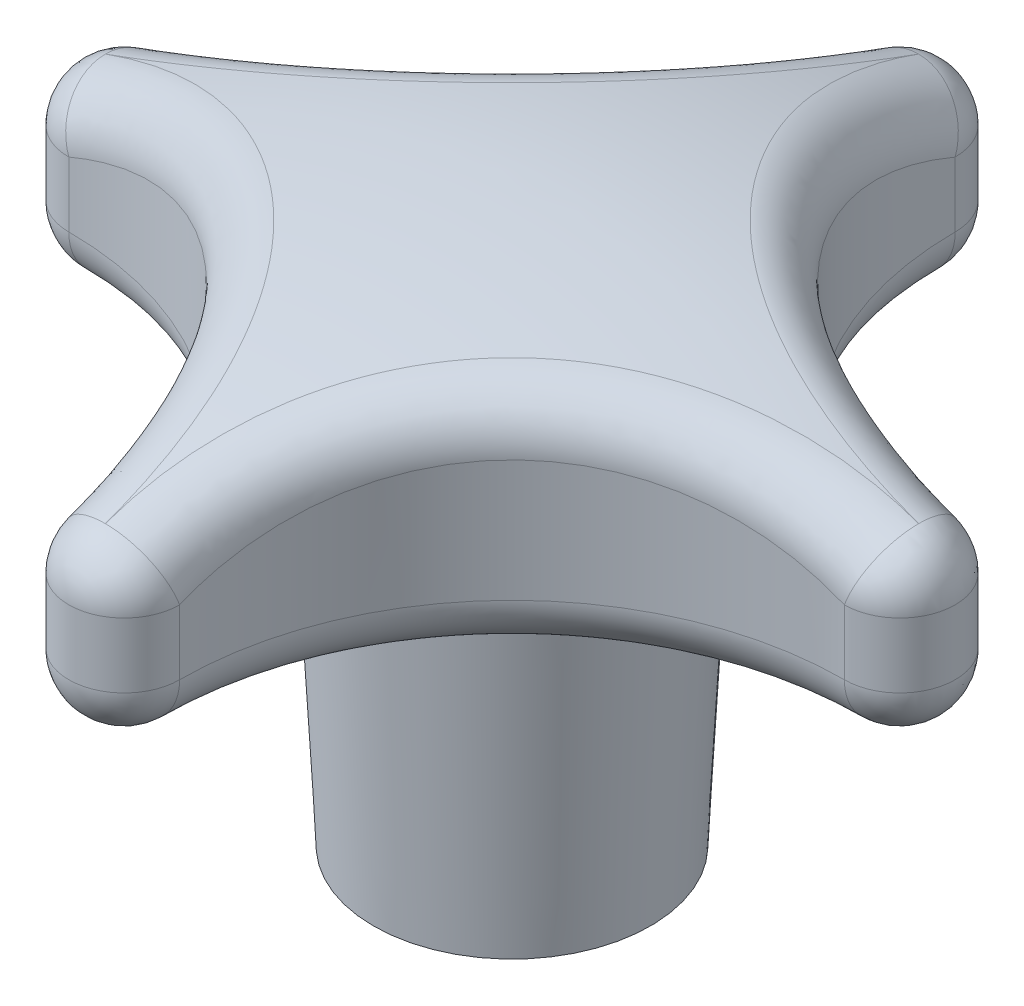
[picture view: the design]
ISO-10303-21;
HEADER;
FILE_DESCRIPTION(('STEP AP214'),'2;1');
FILE_NAME('part.step','',(''),(''),'','','');
FILE_SCHEMA(('AUTOMOTIVE_DESIGN { 1 0 10303 214 1 1 1 1 }'));
ENDSEC;
DATA;
#1=APPLICATION_CONTEXT('core data for automotive mechanical design processes');
#2=APPLICATION_PROTOCOL_DEFINITION('international standard','automotive_design',2000,#1);
#3=PRODUCT_CONTEXT('',#1,'mechanical');
#4=PRODUCT('Part','Part','',(#3));
#5=PRODUCT_RELATED_PRODUCT_CATEGORY('part','',(#4));
#6=PRODUCT_DEFINITION_FORMATION('','',#4);
#7=PRODUCT_DEFINITION_CONTEXT('part definition',#1,'design');
#8=PRODUCT_DEFINITION('design','',#6,#7);
#9=PRODUCT_DEFINITION_SHAPE('','',#8);
#10=(LENGTH_UNIT() NAMED_UNIT(*) SI_UNIT(.MILLI.,.METRE.));
#11=(NAMED_UNIT(*) PLANE_ANGLE_UNIT() SI_UNIT($,.RADIAN.));
#12=(NAMED_UNIT(*) SI_UNIT($,.STERADIAN.) SOLID_ANGLE_UNIT());
#13=UNCERTAINTY_MEASURE_WITH_UNIT(LENGTH_MEASURE(1.E-05),#10,'distance_accuracy_value','');
#14=(GEOMETRIC_REPRESENTATION_CONTEXT(3) GLOBAL_UNCERTAINTY_ASSIGNED_CONTEXT((#13)) GLOBAL_UNIT_ASSIGNED_CONTEXT((#10,
#11,#12)) REPRESENTATION_CONTEXT('',''));
#15=CARTESIAN_POINT('',(0.,0.,0.));
#16=DIRECTION('',(0.,0.,1.));
#17=DIRECTION('',(1.,0.,0.));
#18=AXIS2_PLACEMENT_3D('',#15,#16,#17);
#19=CARTESIAN_POINT('',(0.,-85.7461038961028,0.));
#20=DIRECTION('',(0.,-1.,0.));
#21=DIRECTION('',(1.,0.,0.));
#22=AXIS2_PLACEMENT_3D('',#19,#20,#21);
#23=SPHERICAL_SURFACE('',#22,107.746103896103);
#24=CARTESIAN_POINT('',(-45.4260701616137,5.50948791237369,6.86999713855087));
#25=CARTESIAN_POINT('',(-47.811696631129,10.6709628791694,7.75420284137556));
#26=CARTESIAN_POINT('',(-49.4589084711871,9.95031770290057,2.28783101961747));
#27=CARTESIAN_POINT('',(-44.6147524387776,6.00713444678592,6.56920938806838));
#28=CARTESIAN_POINT('',(-46.9657144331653,11.1176727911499,7.36275900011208));
#29=CARTESIAN_POINT('',(-48.4663091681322,10.4721815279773,1.91983497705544));
#30=CARTESIAN_POINT('',(-43.7857141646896,6.49359463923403,6.30194379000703));
#31=CARTESIAN_POINT('',(-46.0906154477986,11.5594271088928,7.00568573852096));
#32=CARTESIAN_POINT('',(-47.4520298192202,10.9823146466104,1.59285130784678));
#33=CARTESIAN_POINT('',(-42.0970199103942,7.44147869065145,5.83840915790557));
#34=CARTESIAN_POINT('',(-44.3018208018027,12.4219272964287,6.37356108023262));
#35=CARTESIAN_POINT('',(-45.3860121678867,11.9763261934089,1.02574407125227));
#36=CARTESIAN_POINT('',(-41.2373410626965,7.90288317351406,5.6421944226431));
#37=CARTESIAN_POINT('',(-43.3878911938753,12.8432886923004,6.0972131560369));
#38=CARTESIAN_POINT('',(-44.3342458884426,12.4601843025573,0.785686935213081));
#39=CARTESIAN_POINT('',(-39.4912914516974,8.79832737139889,5.32479404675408));
#40=CARTESIAN_POINT('',(-41.5264112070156,13.6623243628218,5.63127781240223));
#41=CARTESIAN_POINT('',(-42.198057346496,13.39920408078,0.397366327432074));
#42=CARTESIAN_POINT('',(-38.6048600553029,9.23229674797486,5.20379475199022));
#43=CARTESIAN_POINT('',(-40.5783554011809,14.0606052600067,5.44061351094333));
#44=CARTESIAN_POINT('',(-41.1135609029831,13.8542919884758,0.249330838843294));
#45=CARTESIAN_POINT('',(-36.8140784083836,10.0683240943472,5.04141375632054));
#46=CARTESIAN_POINT('',(-38.6590868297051,14.8287845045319,5.15153974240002));
#47=CARTESIAN_POINT('',(-38.922645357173,14.7310034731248,0.0506672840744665));
#48=CARTESIAN_POINT('',(-35.9097347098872,10.4703934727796,5.00000346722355));
#49=CARTESIAN_POINT('',(-37.6872830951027,15.199359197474,5.05192286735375));
#50=CARTESIAN_POINT('',(-37.8162342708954,15.1526390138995,4.24193149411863E-06));
#51=CARTESIAN_POINT('',(-34.2235833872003,11.1831344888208,4.99999704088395));
#52=CARTESIAN_POINT('',(-35.8713862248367,15.8572908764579,4.95610858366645));
#53=CARTESIAN_POINT('',(-35.75332774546,15.900064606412,-3.62029357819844E-06));
#54=CARTESIAN_POINT('',(-33.4432400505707,11.4985653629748,5.030154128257));
#55=CARTESIAN_POINT('',(-35.0300796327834,16.1489121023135,4.94625745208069));
#56=CARTESIAN_POINT('',(-34.7986237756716,16.2308454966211,0.0368917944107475));
#57=CARTESIAN_POINT('',(-31.8796288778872,12.101918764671,5.15241994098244));
#58=CARTESIAN_POINT('',(-33.3428848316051,16.7070337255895,4.99814861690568));
#59=CARTESIAN_POINT('',(-32.8856378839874,16.8635602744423,0.18647679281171));
#60=CARTESIAN_POINT('',(-31.0963614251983,12.3898447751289,5.24452081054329));
#61=CARTESIAN_POINT('',(-32.4964091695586,16.9739426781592,5.05933431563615));
#62=CARTESIAN_POINT('',(-31.9273564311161,17.1654978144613,0.299156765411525));
#63=CARTESIAN_POINT('',(-29.5333029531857,12.9358530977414,5.49168913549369));
#64=CARTESIAN_POINT('',(-30.8064360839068,17.4802647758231,5.25446941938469));
#65=CARTESIAN_POINT('',(-30.0150467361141,17.7380768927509,0.601552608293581));
#66=CARTESIAN_POINT('',(-28.7535086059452,13.1939765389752,5.6466684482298));
#67=CARTESIAN_POINT('',(-29.9622746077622,17.7201016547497,5.38787779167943));
#68=CARTESIAN_POINT('',(-29.061014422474,18.0087615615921,0.791160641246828));
#69=CARTESIAN_POINT('',(-27.2019951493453,13.6789429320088,6.02021809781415));
#70=CARTESIAN_POINT('',(-28.2825655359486,18.1707634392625,5.72802045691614));
#71=CARTESIAN_POINT('',(-27.1628293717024,18.5173281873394,1.24817656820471));
#72=CARTESIAN_POINT('',(-26.4302760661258,13.9057857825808,6.23878864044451));
#73=CARTESIAN_POINT('',(-27.4462808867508,18.381951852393,5.9344379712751));
#74=CARTESIAN_POINT('',(-26.2186766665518,18.7552100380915,1.51558471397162));
#75=CARTESIAN_POINT('',(-24.8978685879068,14.3272354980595,6.74049733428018));
#76=CARTESIAN_POINT('',(-25.786177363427,18.7742802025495,6.4214185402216));
#77=CARTESIAN_POINT('',(-24.343866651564,19.1971690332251,2.12939565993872));
#78=CARTESIAN_POINT('',(-24.1372364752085,14.5217101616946,7.02388957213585));
#79=CARTESIAN_POINT('',(-24.9616091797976,18.9556349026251,6.70209323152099));
#80=CARTESIAN_POINT('',(-23.4132781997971,19.4011075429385,2.47610932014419));
#81=CARTESIAN_POINT('',(-22.6364376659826,14.8756740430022,7.65398296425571));
#82=CARTESIAN_POINT('',(-23.3357727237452,19.2856272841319,7.33617749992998));
#83=CARTESIAN_POINT('',(-21.5771395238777,19.7722965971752,3.24699135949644));
#84=CARTESIAN_POINT('',(-21.8962711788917,15.0351629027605,8.00068476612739));
#85=CARTESIAN_POINT('',(-22.5336800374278,19.4345566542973,7.68954504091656));
#86=CARTESIAN_POINT('',(-20.6715895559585,19.9395467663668,3.67116053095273));
#87=CARTESIAN_POINT('',(-20.4426048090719,15.3177605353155,8.75589105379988));
#88=CARTESIAN_POINT('',(-20.9601065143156,19.6983233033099,8.46710027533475));
#89=CARTESIAN_POINT('',(-18.8931146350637,20.2358966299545,4.59511080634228));
#90=CARTESIAN_POINT('',(-19.7291109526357,15.4408611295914,9.16440940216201));
#91=CARTESIAN_POINT('',(-20.1878034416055,19.813394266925,8.89140978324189));
#92=CARTESIAN_POINT('',(-18.0201970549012,20.3649877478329,5.0949088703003));
#93=CARTESIAN_POINT('',(-18.3352752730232,15.6494810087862,10.0407427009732));
#94=CARTESIAN_POINT('',(-18.6813856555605,20.0082837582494,9.80778859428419));
#95=CARTESIAN_POINT('',(-16.314921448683,20.5837598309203,6.16705088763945));
#96=CARTESIAN_POINT('',(-17.6549317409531,15.7350022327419,10.5085545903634));
#97=CARTESIAN_POINT('',(-17.9464641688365,20.0882869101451,10.3001077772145));
#98=CARTESIAN_POINT('',(-15.4825613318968,20.6734428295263,6.73939109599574));
#99=CARTESIAN_POINT('',(-16.3694645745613,15.8640333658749,11.4731368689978));
#100=CARTESIAN_POINT('',(-16.5606211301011,20.2089045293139,11.3199620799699));
#101=CARTESIAN_POINT('',(-13.9098681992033,20.8087530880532,7.91950052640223));
#102=CARTESIAN_POINT('',(-15.7622622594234,15.9095784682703,11.9669404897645));
#103=CARTESIAN_POINT('',(-15.9067072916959,20.2515259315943,11.8444162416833));
#104=CARTESIAN_POINT('',(-13.1669920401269,20.8565145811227,8.5236400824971));
#105=CARTESIAN_POINT('',(-14.5876798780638,15.9659484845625,13.0011495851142));
#106=CARTESIAN_POINT('',(-14.6448156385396,20.3042340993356,12.9461876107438));
#107=CARTESIAN_POINT('',(-11.7299598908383,20.915627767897,9.7889338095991));
#108=CARTESIAN_POINT('',(-14.0202983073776,15.9767747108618,13.5415532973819));
#109=CARTESIAN_POINT('',(-14.0362609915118,20.3143675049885,13.523939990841));
#110=CARTESIAN_POINT('',(-11.0358020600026,20.9269808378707,10.4500858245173));
#111=CARTESIAN_POINT('',(-12.9298092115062,15.9636140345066,14.6648256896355));
#112=CARTESIAN_POINT('',(-12.8702112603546,20.3020608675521,14.7273860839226));
#113=CARTESIAN_POINT('',(-9.7016530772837,20.9131797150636,11.8243432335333));
#114=CARTESIAN_POINT('',(-12.4066932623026,15.9396337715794,15.247686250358));
#115=CARTESIAN_POINT('',(-12.3122116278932,20.2796164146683,15.3535977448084));
#116=CARTESIAN_POINT('',(-9.06165161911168,20.8880324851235,12.5374386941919));
#117=CARTESIAN_POINT('',(-11.4084308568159,15.8570839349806,16.4514359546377));
#118=CARTESIAN_POINT('',(-11.2515126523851,20.2024357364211,16.6486816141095));
#119=CARTESIAN_POINT('',(-7.84033654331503,20.8014654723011,14.0101553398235));
#120=CARTESIAN_POINT('',(-10.9332840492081,15.7985146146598,17.072324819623));
#121=CARTESIAN_POINT('',(-10.7484136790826,20.1476334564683,17.3181539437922));
#122=CARTESIAN_POINT('',(-7.25902249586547,20.7400459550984,14.7697761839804));
#123=CARTESIAN_POINT('',(-10.0473360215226,15.6495152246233,18.3285291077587));
#124=CARTESIAN_POINT('',(-9.81505699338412,20.0083863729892,18.6737386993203));
#125=CARTESIAN_POINT('',(-6.17511742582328,20.5837957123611,16.3066679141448));
#126=CARTESIAN_POINT('',(-9.63505856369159,15.5600678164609,18.9628904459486));
#127=CARTESIAN_POINT('',(-9.38280219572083,19.9247412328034,19.3594343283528));
#128=CARTESIAN_POINT('',(-5.67072031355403,20.4899954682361,17.0827715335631));
#129=CARTESIAN_POINT('',(-8.86106882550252,15.3497862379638,20.2580402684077));
#130=CARTESIAN_POINT('',(-8.57645584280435,19.7283409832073,20.7599290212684));
#131=CARTESIAN_POINT('',(-4.72378959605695,20.2694808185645,18.6673108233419));
#132=CARTESIAN_POINT('',(-8.4993548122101,15.2289531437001,20.9188278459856));
#133=CARTESIAN_POINT('',(-8.2021975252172,19.6154327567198,21.475355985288));
#134=CARTESIAN_POINT('',(-4.28125387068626,20.1427675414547,19.4757453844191));
#135=CARTESIAN_POINT('',(-7.82831467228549,14.9568802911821,22.2617587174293));
#136=CARTESIAN_POINT('',(-7.51385404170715,19.3615408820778,22.9293610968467));
#137=CARTESIAN_POINT('',(-3.46027590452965,19.8574546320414,21.1187419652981));
#138=CARTESIAN_POINT('',(-7.51897208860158,14.8056501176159,22.9438952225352));
#139=CARTESIAN_POINT('',(-7.19969016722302,19.2203717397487,23.6685731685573));
#140=CARTESIAN_POINT('',(-3.08181352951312,19.6988650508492,21.9532956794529));
#141=CARTESIAN_POINT('',(-6.95365023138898,14.4738834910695,24.3248415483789));
#142=CARTESIAN_POINT('',(-6.63258179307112,18.9111185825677,25.164628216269));
#143=CARTESIAN_POINT('',(-2.39017563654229,19.3509534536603,23.6428019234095));
#144=CARTESIAN_POINT('',(-6.69767385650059,14.2933454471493,25.0236522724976));
#145=CARTESIAN_POINT('',(-6.37968611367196,18.7428037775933,25.9221071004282));
#146=CARTESIAN_POINT('',(-2.07700366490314,19.1616297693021,24.4977555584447));
#147=CARTESIAN_POINT('',(-6.2218009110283,13.8890685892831,26.4880551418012));
#148=CARTESIAN_POINT('',(-5.91827932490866,18.3664012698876,27.5088463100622));
#149=CARTESIAN_POINT('',(-1.49480123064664,18.7376793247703,26.2893659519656));
#150=CARTESIAN_POINT('',(-6.0062707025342,13.6630595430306,27.2546075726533));
#151=CARTESIAN_POINT('',(-5.71503754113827,18.1560011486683,28.3395120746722));
#152=CARTESIAN_POINT('',(-1.23111275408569,18.5006718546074,27.22719756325));
#153=CARTESIAN_POINT('',(-5.63789951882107,13.1802267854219,28.7955848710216));
#154=CARTESIAN_POINT('',(-5.38021584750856,17.7073398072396,30.0077810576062));
#155=CARTESIAN_POINT('',(-0.780432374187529,17.9943426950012,29.1124922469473));
#156=CARTESIAN_POINT('',(-5.48506193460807,12.9234014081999,29.570010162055));
#157=CARTESIAN_POINT('',(-5.2489528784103,17.4687206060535,30.8461047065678));
#158=CARTESIAN_POINT('',(-0.593444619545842,17.7250192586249,30.0599558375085));
#159=CARTESIAN_POINT('',(-5.2412510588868,12.3803396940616,31.1224643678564));
#160=CARTESIAN_POINT('',(-5.05706521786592,16.9651457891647,32.5245765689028));
#161=CARTESIAN_POINT('',(-0.295156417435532,17.1555301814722,31.9592918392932));
#162=CARTESIAN_POINT('',(-5.15038405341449,12.0940537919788,31.900497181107));
#163=CARTESIAN_POINT('',(-4.99699511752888,16.6997669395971,33.3653727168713));
#164=CARTESIAN_POINT('',(-0.183986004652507,16.8553125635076,32.9111690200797));
#165=CARTESIAN_POINT('',(-5.02975303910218,11.4943592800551,33.4536442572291));
#166=CARTESIAN_POINT('',(-4.94638911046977,16.1450398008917,35.0412500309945));
#167=CARTESIAN_POINT('',(-0.0364010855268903,16.2264347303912,34.8113527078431));
#168=CARTESIAN_POINT('',(-4.99999689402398,11.1809471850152,34.2287581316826));
#169=CARTESIAN_POINT('',(-4.95639957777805,15.8552909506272,35.8769063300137));
#170=CARTESIAN_POINT('',(3.79996774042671E-06,15.8977708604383,35.7596587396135));
#171=CARTESIAN_POINT('',(-5.00000366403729,10.4703601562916,35.9098133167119));
#172=CARTESIAN_POINT('',(-5.05192769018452,15.1993281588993,37.6873684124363));
#173=CARTESIAN_POINT('',(-4.48272072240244E-06,15.1526040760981,37.8163304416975));
#174=CARTESIAN_POINT('',(-5.04142115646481,10.068252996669,36.8142382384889));
#175=CARTESIAN_POINT('',(-5.15155756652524,14.8287186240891,38.6592594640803));
#176=CARTESIAN_POINT('',(-0.050676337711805,14.730928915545,38.9228408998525));
#177=CARTESIAN_POINT('',(-5.20383148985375,9.23214063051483,38.6051869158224));
#178=CARTESIAN_POINT('',(-5.44067467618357,14.0604614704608,40.5787065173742));
#179=CARTESIAN_POINT('',(-0.249375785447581,13.854128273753,41.1139607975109));
#180=CARTESIAN_POINT('',(-5.32485383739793,8.79812364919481,39.491703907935));
#181=CARTESIAN_POINT('',(-5.6313706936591,13.6621370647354,41.5268531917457));
#182=CARTESIAN_POINT('',(-0.397439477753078,13.3989904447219,42.1985619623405));
#183=CARTESIAN_POINT('',(-5.64228458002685,7.90266378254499,41.2377536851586));
#184=CARTESIAN_POINT('',(-6.09734068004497,12.8430887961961,43.3883290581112));
#185=CARTESIAN_POINT('',(-0.785797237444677,12.4599542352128,44.3347507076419));
#186=CARTESIAN_POINT('',(-5.83849231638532,7.44129663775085,42.0973517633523));
#187=CARTESIAN_POINT('',(-6.3736757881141,12.4217618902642,44.302171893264));
#188=CARTESIAN_POINT('',(-1.02584581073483,11.9761352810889,45.3864181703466));
#189=CARTESIAN_POINT('',(-6.30199730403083,6.49349722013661,43.7858801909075));
#190=CARTESIAN_POINT('',(-7.0057567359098,11.5593392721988,46.0907894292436));
#191=CARTESIAN_POINT('',(-1.59291677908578,10.9822124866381,47.4522329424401));
#192=CARTESIAN_POINT('',(-6.56923949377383,6.00708459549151,44.6148337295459));
#193=CARTESIAN_POINT('',(-7.3627979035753,11.1176283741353,46.9657985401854));
#194=CARTESIAN_POINT('',(-1.91987180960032,10.4721292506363,48.4664086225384));
#195=CARTESIAN_POINT('',(-6.86999713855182,5.50948791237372,45.4260701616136));
#196=CARTESIAN_POINT('',(-7.75420284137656,10.6709628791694,47.8116966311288));
#197=CARTESIAN_POINT('',(-2.2878310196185,9.95031770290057,49.458908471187));
#198=(BOUNDED_SURFACE() B_SPLINE_SURFACE(3,2,((#24,#25,#26),(#27,#28,#29),(#30,#31,#32),(#33,
#34,#35),(#36,#37,#38),(#39,#40,#41),(#42,#43,#44),(#45,#46,#47),(#48,#49,#50),(#51,#52,#53),
(#54,#55,#56),(#57,#58,#59),(#60,#61,#62),(#63,#64,#65),(#66,#67,#68),(#69,#70,#71),(#72,#73,
#74),(#75,#76,#77),(#78,#79,#80),(#81,#82,#83),(#84,#85,#86),(#87,#88,#89),(#90,#91,#92),(#93,
#94,#95),(#96,#97,#98),(#99,#100,#101),(#102,#103,#104),(#105,#106,#107),(#108,#109,#110),(#111,
#112,#113),(#114,#115,#116),(#117,#118,#119),(#120,#121,#122),(#123,#124,#125),(#126,#127,#128),
(#129,#130,#131),(#132,#133,#134),(#135,#136,#137),(#138,#139,#140),(#141,#142,#143),(#144,#145,
#146),(#147,#148,#149),(#150,#151,#152),(#153,#154,#155),(#156,#157,#158),(#159,#160,#161),
(#162,#163,#164),(#165,#166,#167),(#168,#169,#170),(#171,#172,#173),(#174,#175,#176),(#177,#178,
#179),(#180,#181,#182),(#183,#184,#185),(#186,#187,#188),(#189,#190,#191),(#192,#193,#194),
(#195,#196,#197)),.UNSPECIFIED.,.F.,.F.,.F.) B_SPLINE_SURFACE_WITH_KNOTS((4,2,2,2,2,2,2,2,2,2,2,
2,2,2,2,2,2,2,2,2,2,2,2,2,2,2,2,2,4),(3,3),(0.,3.3759280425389,6.7544306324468,10.1412704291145,
13.5268934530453,16.4163665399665,19.3054732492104,22.190543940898,25.0756239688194,
27.9722127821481,30.8688312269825,33.7661002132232,36.663219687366,39.4024819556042,
42.1416406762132,44.8802769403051,47.6188931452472,50.2773563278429,52.9357283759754,
55.5932635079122,58.2509429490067,61.1157387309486,63.9806894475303,66.8505415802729,
69.7207629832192,73.1066860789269,76.4938649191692,79.8720661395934,83.247656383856),(0.,1.),
.UNSPECIFIED.) GEOMETRIC_REPRESENTATION_ITEM() RATIONAL_B_SPLINE_SURFACE(((1.,0.655888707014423,
1.),(1.,0.660702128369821,1.),(1.,0.665393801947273,1.),(1.,0.674513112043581,1.),(1.,
0.678940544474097,1.),(1.,0.687513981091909,1.),(1.,0.691659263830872,1.),(1.,0.699629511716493,
1.),(1.,0.703454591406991,1.),(1.,0.710223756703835,1.),(1.,0.713214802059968,1.),(1.,
0.718928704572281,1.),(1.,0.721651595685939,1.),(1.,0.726809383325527,1.),(1.,0.729244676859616,
1.),(1.,0.733815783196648,1.),(1.,0.735951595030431,1.),(1.,0.739916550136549,1.),(1.,
0.741744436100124,1.),(1.,0.745069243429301,1.),(1.,0.746566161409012,1.),(1.,0.749217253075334,
1.),(1.,0.7503713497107,1.),(1.,0.752326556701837,1.),(1.,0.753127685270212,1.),(1.,
0.754336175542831,1.),(1.,0.754762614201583,1.),(1.,0.755290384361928,1.),(1.,0.755391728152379,
1.),(1.,0.755268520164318,1.),(1.,0.755044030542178,1.),(1.,0.75427107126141,1.),(1.,
0.753722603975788,1.),(1.,0.75232680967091,1.),(1.,0.751488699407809,1.),(1.,0.749517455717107,
1.),(1.,0.748384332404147,1.),(1.,0.745831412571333,1.),(1.,0.744411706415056,1.),(1.,
0.741294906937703,1.),(1.,0.739597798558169,1.),(1.,0.73579422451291,1.),(1.,0.733666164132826,
1.),(1.,0.729114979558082,1.),(1.,0.726691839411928,1.),(1.,0.721561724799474,1.),(1.,
0.718854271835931,1.),(1.,0.713174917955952,1.),(1.,0.71020298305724,1.),(1.,0.703454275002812,
1.),(1.,0.699628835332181,1.),(1.,0.691657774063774,1.),(1.,0.687512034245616,1.),(1.,
0.67893844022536,1.),(1.,0.674511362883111,1.),(1.,0.665392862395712,1.),(1.,0.660701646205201,
1.),(1.,0.655888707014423,1.))) REPRESENTATION_ITEM('') SURFACE());
#199=CARTESIAN_POINT('',(-49.4589084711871,9.95031770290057,2.28783101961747));
#200=CARTESIAN_POINT('',(-48.4663091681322,10.4721815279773,1.91983497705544));
#201=CARTESIAN_POINT('',(-47.4520298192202,10.9823146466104,1.59285130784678));
#202=CARTESIAN_POINT('',(-45.3860121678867,11.9763261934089,1.02574407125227));
#203=CARTESIAN_POINT('',(-44.3342458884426,12.4601843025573,0.785686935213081));
#204=CARTESIAN_POINT('',(-42.198057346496,13.39920408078,0.397366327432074));
#205=CARTESIAN_POINT('',(-41.1135609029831,13.8542919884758,0.249330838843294));
#206=CARTESIAN_POINT('',(-38.922645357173,14.7310034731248,0.0506672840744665));
#207=CARTESIAN_POINT('',(-37.8162342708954,15.1526390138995,4.24193149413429E-06));
#208=CARTESIAN_POINT('',(-35.75332774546,15.900064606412,-3.62029357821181E-06));
#209=CARTESIAN_POINT('',(-34.7986237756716,16.2308454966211,0.0368917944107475));
#210=CARTESIAN_POINT('',(-32.8856378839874,16.8635602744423,0.18647679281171));
#211=CARTESIAN_POINT('',(-31.9273564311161,17.1654978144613,0.299156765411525));
#212=CARTESIAN_POINT('',(-30.0150467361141,17.7380768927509,0.601552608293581));
#213=CARTESIAN_POINT('',(-29.061014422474,18.0087615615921,0.791160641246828));
#214=CARTESIAN_POINT('',(-27.1628293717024,18.5173281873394,1.24817656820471));
#215=CARTESIAN_POINT('',(-26.2186766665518,18.7552100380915,1.51558471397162));
#216=CARTESIAN_POINT('',(-24.343866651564,19.1971690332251,2.12939565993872));
#217=CARTESIAN_POINT('',(-23.4132781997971,19.4011075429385,2.47610932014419));
#218=CARTESIAN_POINT('',(-21.5771395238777,19.7722965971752,3.24699135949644));
#219=CARTESIAN_POINT('',(-20.6715895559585,19.9395467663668,3.67116053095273));
#220=CARTESIAN_POINT('',(-18.8931146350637,20.2358966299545,4.59511080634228));
#221=CARTESIAN_POINT('',(-18.0201970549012,20.3649877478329,5.0949088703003));
#222=CARTESIAN_POINT('',(-16.314921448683,20.5837598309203,6.16705088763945));
#223=CARTESIAN_POINT('',(-15.4825613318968,20.6734428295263,6.73939109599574));
#224=CARTESIAN_POINT('',(-13.9098681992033,20.8087530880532,7.91950052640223));
#225=CARTESIAN_POINT('',(-13.1669920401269,20.8565145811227,8.5236400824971));
#226=CARTESIAN_POINT('',(-11.7299598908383,20.915627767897,9.7889338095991));
#227=CARTESIAN_POINT('',(-11.0358020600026,20.9269808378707,10.4500858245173));
#228=CARTESIAN_POINT('',(-9.70165307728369,20.9131797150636,11.8243432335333));
#229=CARTESIAN_POINT('',(-9.06165161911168,20.8880324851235,12.5374386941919));
#230=CARTESIAN_POINT('',(-7.84033654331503,20.8014654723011,14.0101553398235));
#231=CARTESIAN_POINT('',(-7.25902249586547,20.7400459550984,14.7697761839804));
#232=CARTESIAN_POINT('',(-6.17511742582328,20.5837957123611,16.3066679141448));
#233=CARTESIAN_POINT('',(-5.67072031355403,20.4899954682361,17.0827715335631));
#234=CARTESIAN_POINT('',(-4.72378959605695,20.2694808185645,18.6673108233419));
#235=CARTESIAN_POINT('',(-4.28125387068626,20.1427675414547,19.4757453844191));
#236=CARTESIAN_POINT('',(-3.46027590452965,19.8574546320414,21.1187419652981));
#237=CARTESIAN_POINT('',(-3.08181352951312,19.6988650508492,21.9532956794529));
#238=CARTESIAN_POINT('',(-2.39017563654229,19.3509534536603,23.6428019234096));
#239=CARTESIAN_POINT('',(-2.07700366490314,19.1616297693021,24.4977555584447));
#240=CARTESIAN_POINT('',(-1.49480123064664,18.7376793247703,26.2893659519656));
#241=CARTESIAN_POINT('',(-1.23111275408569,18.5006718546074,27.22719756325));
#242=CARTESIAN_POINT('',(-0.780432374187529,17.9943426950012,29.1124922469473));
#243=CARTESIAN_POINT('',(-0.593444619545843,17.7250192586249,30.0599558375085));
#244=CARTESIAN_POINT('',(-0.295156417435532,17.1555301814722,31.9592918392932));
#245=CARTESIAN_POINT('',(-0.183986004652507,16.8553125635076,32.9111690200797));
#246=CARTESIAN_POINT('',(-0.0364010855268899,16.2264347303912,34.8113527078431));
#247=CARTESIAN_POINT('',(3.79996774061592E-06,15.8977708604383,35.7596587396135));
#248=CARTESIAN_POINT('',(-4.48272072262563E-06,15.1526040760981,37.8163304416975));
#249=CARTESIAN_POINT('',(-0.050676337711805,14.730928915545,38.9228408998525));
#250=CARTESIAN_POINT('',(-0.249375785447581,13.854128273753,41.1139607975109));
#251=CARTESIAN_POINT('',(-0.397439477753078,13.3989904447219,42.1985619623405));
#252=CARTESIAN_POINT('',(-0.785797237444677,12.4599542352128,44.3347507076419));
#253=CARTESIAN_POINT('',(-1.02584581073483,11.9761352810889,45.3864181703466));
#254=CARTESIAN_POINT('',(-1.59291677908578,10.9822124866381,47.4522329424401));
#255=CARTESIAN_POINT('',(-1.91987180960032,10.4721292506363,48.4664086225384));
#256=CARTESIAN_POINT('',(-2.2878310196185,9.95031770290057,49.458908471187));
#257=B_SPLINE_CURVE_WITH_KNOTS('',3,(#199,#200,#201,#202,#203,#204,#205,#206,#207,#208,#209,
#210,#211,#212,#213,#214,#215,#216,#217,#218,#219,#220,#221,#222,#223,#224,#225,#226,#227,#228,
#229,#230,#231,#232,#233,#234,#235,#236,#237,#238,#239,#240,#241,#242,#243,#244,#245,#246,#247,
#248,#249,#250,#251,#252,#253,#254,#255,#256),.UNSPECIFIED.,.F.,.F.,(4,2,2,2,2,2,2,2,2,2,2,2,2,
2,2,2,2,2,2,2,2,2,2,2,2,2,2,2,4),(0.,3.3759280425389,6.7544306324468,10.1412704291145,
13.5268934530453,16.4163665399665,19.3054732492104,22.190543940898,25.0756239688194,
27.9722127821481,30.8688312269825,33.7661002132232,36.663219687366,39.4024819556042,
42.1416406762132,44.8802769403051,47.6188931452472,50.2773563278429,52.9357283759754,
55.5932635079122,58.2509429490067,61.1157387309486,63.9806894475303,66.8505415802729,
69.7207629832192,73.1066860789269,76.4938649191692,79.8720661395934,83.247656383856),.UNSPECIFIED.);
#258=CARTESIAN_POINT('',(-36.7032276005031,15.5558999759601,-3.84543011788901E-13));
#259=VERTEX_POINT('',#258);
#260=CARTESIAN_POINT('',(-3.88185023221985E-13,15.5558999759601,36.7032276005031));
#261=VERTEX_POINT('',#260);
#262=EDGE_CURVE('E352',#259,#261,#257,.T.);
#263=ORIENTED_EDGE('',*,*,#262,.T.);
#264=CARTESIAN_POINT('',(6.86999713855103,5.50948791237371,45.4260701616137));
#265=CARTESIAN_POINT('',(7.75420284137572,10.6709628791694,47.8116966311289));
#266=CARTESIAN_POINT('',(2.28783101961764,9.95031770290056,49.4589084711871));
#267=CARTESIAN_POINT('',(6.56920938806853,6.0071344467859,44.6147524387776));
#268=CARTESIAN_POINT('',(7.36275900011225,11.1176727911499,46.9657144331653));
#269=CARTESIAN_POINT('',(1.91983497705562,10.4721815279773,48.4663091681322));
#270=CARTESIAN_POINT('',(6.30194379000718,6.49359463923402,43.7857141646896));
#271=CARTESIAN_POINT('',(7.00568573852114,11.5594271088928,46.0906154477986));
#272=CARTESIAN_POINT('',(1.59285130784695,10.9823146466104,47.4520298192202));
#273=CARTESIAN_POINT('',(5.83840915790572,7.44147869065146,42.0970199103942));
#274=CARTESIAN_POINT('',(6.37356108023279,12.4219272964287,44.3018208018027));
#275=CARTESIAN_POINT('',(1.02574407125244,11.9763261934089,45.3860121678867));
#276=CARTESIAN_POINT('',(5.64219442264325,7.90288317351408,41.2373410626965));
#277=CARTESIAN_POINT('',(6.09721315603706,12.8432886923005,43.3878911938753));
#278=CARTESIAN_POINT('',(0.78568693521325,12.4601843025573,44.3342458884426));
#279=CARTESIAN_POINT('',(5.32479404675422,8.79832737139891,39.4912914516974));
#280=CARTESIAN_POINT('',(5.63127781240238,13.6623243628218,41.5264112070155));
#281=CARTESIAN_POINT('',(0.397366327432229,13.39920408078,42.198057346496));
#282=CARTESIAN_POINT('',(5.20379475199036,9.23229674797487,38.6048600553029));
#283=CARTESIAN_POINT('',(5.44061351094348,14.0606052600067,40.5783554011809));
#284=CARTESIAN_POINT('',(0.249330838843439,13.8542919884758,41.1135609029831));
#285=CARTESIAN_POINT('',(5.04141375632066,10.0683240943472,36.8140784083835));
#286=CARTESIAN_POINT('',(5.15153974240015,14.8287845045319,38.6590868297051));
#287=CARTESIAN_POINT('',(0.0506672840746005,14.7310034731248,38.922645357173));
#288=CARTESIAN_POINT('',(5.00000346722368,10.4703934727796,35.9097347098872));
#289=CARTESIAN_POINT('',(5.05192286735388,15.199359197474,37.6872830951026));
#290=CARTESIAN_POINT('',(4.24193162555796E-06,15.1526390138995,37.8162342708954));
#291=CARTESIAN_POINT('',(4.99999704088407,11.1831344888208,34.2235833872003));
#292=CARTESIAN_POINT('',(4.95610858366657,15.8572908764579,35.8713862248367));
#293=CARTESIAN_POINT('',(-3.62029345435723E-06,15.900064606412,35.75332774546));
#294=CARTESIAN_POINT('',(5.03015412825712,11.4985653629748,33.4432400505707));
#295=CARTESIAN_POINT('',(4.94625745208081,16.1489121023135,35.0300796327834));
#296=CARTESIAN_POINT('',(0.0368917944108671,16.2308454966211,34.7986237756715));
#297=CARTESIAN_POINT('',(5.15241994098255,12.101918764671,31.8796288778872));
#298=CARTESIAN_POINT('',(4.99814861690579,16.7070337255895,33.3428848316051));
#299=CARTESIAN_POINT('',(0.186476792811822,16.8635602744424,32.8856378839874));
#300=CARTESIAN_POINT('',(5.2445208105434,12.3898447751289,31.0963614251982));
#301=CARTESIAN_POINT('',(5.05933431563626,16.9739426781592,32.4964091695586));
#302=CARTESIAN_POINT('',(0.299156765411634,17.1654978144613,31.9273564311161));
#303=CARTESIAN_POINT('',(5.49168913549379,12.9358530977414,29.5333029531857));
#304=CARTESIAN_POINT('',(5.25446941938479,17.4802647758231,30.8064360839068));
#305=CARTESIAN_POINT('',(0.601552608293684,17.7380768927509,30.0150467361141));
#306=CARTESIAN_POINT('',(5.6466684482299,13.1939765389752,28.7535086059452));
#307=CARTESIAN_POINT('',(5.38787779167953,17.7201016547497,29.9622746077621));
#308=CARTESIAN_POINT('',(0.791160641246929,18.0087615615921,29.061014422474));
#309=CARTESIAN_POINT('',(6.02021809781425,13.6789429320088,27.2019951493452));
#310=CARTESIAN_POINT('',(5.72802045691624,18.1707634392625,28.2825655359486));
#311=CARTESIAN_POINT('',(1.24817656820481,18.5173281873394,27.1628293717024));
#312=CARTESIAN_POINT('',(6.23878864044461,13.9057857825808,26.4302760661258));
#313=CARTESIAN_POINT('',(5.93443797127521,18.381951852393,27.4462808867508));
#314=CARTESIAN_POINT('',(1.51558471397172,18.7552100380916,26.2186766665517));
#315=CARTESIAN_POINT('',(6.74049733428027,14.3272354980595,24.8978685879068));
#316=CARTESIAN_POINT('',(6.42141854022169,18.7742802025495,25.7861773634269));
#317=CARTESIAN_POINT('',(2.12939565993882,19.1971690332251,24.343866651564));
#318=CARTESIAN_POINT('',(7.02388957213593,14.5217101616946,24.1372364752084));
#319=CARTESIAN_POINT('',(6.70209323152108,18.9556349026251,24.9616091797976));
#320=CARTESIAN_POINT('',(2.47610932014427,19.4011075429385,23.4132781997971));
#321=CARTESIAN_POINT('',(7.65398296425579,14.8756740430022,22.6364376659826));
#322=CARTESIAN_POINT('',(7.33617749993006,19.2856272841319,23.3357727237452));
#323=CARTESIAN_POINT('',(3.24699135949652,19.7722965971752,21.5771395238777));
#324=CARTESIAN_POINT('',(8.00068476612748,15.0351629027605,21.8962711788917));
#325=CARTESIAN_POINT('',(7.68954504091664,19.4345566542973,22.5336800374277));
#326=CARTESIAN_POINT('',(3.67116053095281,19.9395467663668,20.6715895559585));
#327=CARTESIAN_POINT('',(8.75589105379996,15.3177605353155,20.4426048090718));
#328=CARTESIAN_POINT('',(8.46710027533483,19.6983233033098,20.9601065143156));
#329=CARTESIAN_POINT('',(4.59511080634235,20.2358966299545,18.8931146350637));
#330=CARTESIAN_POINT('',(9.16440940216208,15.4408611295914,19.7291109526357));
#331=CARTESIAN_POINT('',(8.89140978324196,19.813394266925,20.1878034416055));
#332=CARTESIAN_POINT('',(5.09490887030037,20.3649877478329,18.0201970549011));
#333=CARTESIAN_POINT('',(10.0407427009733,15.6494810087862,18.3352752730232));
#334=CARTESIAN_POINT('',(9.80778859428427,20.0082837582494,18.6813856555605));
#335=CARTESIAN_POINT('',(6.16705088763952,20.5837598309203,16.314921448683));
#336=CARTESIAN_POINT('',(10.5085545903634,15.7350022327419,17.654931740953));
#337=CARTESIAN_POINT('',(10.3001077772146,20.0882869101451,17.9464641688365));
#338=CARTESIAN_POINT('',(6.73939109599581,20.6734428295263,15.4825613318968));
#339=CARTESIAN_POINT('',(11.4731368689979,15.8640333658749,16.3694645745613));
#340=CARTESIAN_POINT('',(11.3199620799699,20.2089045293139,16.560621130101));
#341=CARTESIAN_POINT('',(7.9195005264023,20.8087530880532,13.9098681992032));
#342=CARTESIAN_POINT('',(11.9669404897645,15.9095784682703,15.7622622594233));
#343=CARTESIAN_POINT('',(11.8444162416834,20.2515259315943,15.9067072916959));
#344=CARTESIAN_POINT('',(8.52364008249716,20.8565145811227,13.1669920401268));
#345=CARTESIAN_POINT('',(13.0011495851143,15.9659484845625,14.5876798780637));
#346=CARTESIAN_POINT('',(12.9461876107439,20.3042340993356,14.6448156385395));
#347=CARTESIAN_POINT('',(9.78893380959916,20.915627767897,11.7299598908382));
#348=CARTESIAN_POINT('',(13.541553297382,15.9767747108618,14.0202983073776));
#349=CARTESIAN_POINT('',(13.5239399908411,20.3143675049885,14.0362609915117));
#350=CARTESIAN_POINT('',(10.4500858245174,20.9269808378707,11.0358020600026));
#351=CARTESIAN_POINT('',(14.6648256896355,15.9636140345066,12.9298092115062));
#352=CARTESIAN_POINT('',(14.7273860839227,20.3020608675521,12.8702112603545));
#353=CARTESIAN_POINT('',(11.8243432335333,20.9131797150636,9.70165307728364));
#354=CARTESIAN_POINT('',(15.2476862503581,15.9396337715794,12.4066932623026));
#355=CARTESIAN_POINT('',(15.3535977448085,20.2796164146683,12.3122116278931));
#356=CARTESIAN_POINT('',(12.537438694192,20.8880324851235,9.06165161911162));
#357=CARTESIAN_POINT('',(16.4514359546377,15.8570839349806,11.4084308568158));
#358=CARTESIAN_POINT('',(16.6486816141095,20.2024357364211,11.251512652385));
#359=CARTESIAN_POINT('',(14.0101553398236,20.8014654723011,7.84033654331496));
#360=CARTESIAN_POINT('',(17.0723248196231,15.7985146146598,10.933284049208));
#361=CARTESIAN_POINT('',(17.3181539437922,20.1476334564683,10.7484136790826));
#362=CARTESIAN_POINT('',(14.7697761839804,20.7400459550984,7.2590224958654));
#363=CARTESIAN_POINT('',(18.3285291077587,15.6495152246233,10.0473360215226));
#364=CARTESIAN_POINT('',(18.6737386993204,20.0083863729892,9.81505699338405));
#365=CARTESIAN_POINT('',(16.3066679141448,20.5837957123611,6.17511742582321));
#366=CARTESIAN_POINT('',(18.9628904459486,15.5600678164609,9.63505856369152));
#367=CARTESIAN_POINT('',(19.3594343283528,19.9247412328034,9.38280219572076));
#368=CARTESIAN_POINT('',(17.0827715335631,20.4899954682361,5.67072031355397));
#369=CARTESIAN_POINT('',(20.2580402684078,15.3497862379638,8.86106882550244));
#370=CARTESIAN_POINT('',(20.7599290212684,19.7283409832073,8.57645584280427));
#371=CARTESIAN_POINT('',(18.6673108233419,20.2694808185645,4.72378959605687));
#372=CARTESIAN_POINT('',(20.9188278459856,15.2289531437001,8.49935481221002));
#373=CARTESIAN_POINT('',(21.4753559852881,19.6154327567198,8.20219752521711));
#374=CARTESIAN_POINT('',(19.4757453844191,20.1427675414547,4.28125387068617));
#375=CARTESIAN_POINT('',(22.2617587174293,14.9568802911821,7.8283146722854));
#376=CARTESIAN_POINT('',(22.9293610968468,19.3615408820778,7.51385404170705));
#377=CARTESIAN_POINT('',(21.1187419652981,19.8574546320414,3.46027590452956));
#378=CARTESIAN_POINT('',(22.9438952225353,14.8056501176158,7.51897208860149));
#379=CARTESIAN_POINT('',(23.6685731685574,19.2203717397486,7.19969016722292));
#380=CARTESIAN_POINT('',(21.9532956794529,19.6988650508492,3.08181352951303));
#381=CARTESIAN_POINT('',(24.324841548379,14.4738834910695,6.95365023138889));
#382=CARTESIAN_POINT('',(25.164628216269,18.9111185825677,6.63258179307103));
#383=CARTESIAN_POINT('',(23.6428019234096,19.3509534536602,2.3901756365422));
#384=CARTESIAN_POINT('',(25.0236522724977,14.2933454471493,6.6976738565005));
#385=CARTESIAN_POINT('',(25.9221071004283,18.7428037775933,6.37968611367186));
#386=CARTESIAN_POINT('',(24.4977555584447,19.1616297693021,2.07700366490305));
#387=CARTESIAN_POINT('',(26.4880551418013,13.8890685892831,6.22180091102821));
#388=CARTESIAN_POINT('',(27.5088463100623,18.3664012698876,5.91827932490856));
#389=CARTESIAN_POINT('',(26.2893659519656,18.7376793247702,1.49480123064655));
#390=CARTESIAN_POINT('',(27.2546075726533,13.6630595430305,6.0062707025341));
#391=CARTESIAN_POINT('',(28.3395120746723,18.1560011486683,5.71503754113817));
#392=CARTESIAN_POINT('',(27.22719756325,18.5006718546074,1.23111275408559));
#393=CARTESIAN_POINT('',(28.7955848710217,13.1802267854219,5.63789951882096));
#394=CARTESIAN_POINT('',(30.0077810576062,17.7073398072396,5.38021584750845));
#395=CARTESIAN_POINT('',(29.1124922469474,17.9943426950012,0.780432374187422));
#396=CARTESIAN_POINT('',(29.5700101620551,12.9234014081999,5.48506193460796));
#397=CARTESIAN_POINT('',(30.8461047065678,17.4687206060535,5.24895287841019));
#398=CARTESIAN_POINT('',(30.0599558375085,17.7250192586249,0.593444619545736));
#399=CARTESIAN_POINT('',(31.1224643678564,12.3803396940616,5.24125105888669));
#400=CARTESIAN_POINT('',(32.5245765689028,16.9651457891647,5.0570652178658));
#401=CARTESIAN_POINT('',(31.9592918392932,17.1555301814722,0.295156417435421));
#402=CARTESIAN_POINT('',(31.900497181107,12.0940537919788,5.15038405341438));
#403=CARTESIAN_POINT('',(33.3653727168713,16.6997669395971,4.99699511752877));
#404=CARTESIAN_POINT('',(32.9111690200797,16.8553125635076,0.183986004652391));
#405=CARTESIAN_POINT('',(33.4536442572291,11.4943592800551,5.02975303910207));
#406=CARTESIAN_POINT('',(35.0412500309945,16.1450398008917,4.94638911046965));
#407=CARTESIAN_POINT('',(34.811352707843,16.2264347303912,0.0364010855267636));
#408=CARTESIAN_POINT('',(34.2287581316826,11.1809471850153,4.99999689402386));
#409=CARTESIAN_POINT('',(35.8769063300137,15.8552909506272,4.95639957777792));
#410=CARTESIAN_POINT('',(35.7596587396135,15.8977708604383,-3.79996787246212E-06));
#411=CARTESIAN_POINT('',(35.9098133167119,10.4703601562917,5.00000366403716));
#412=CARTESIAN_POINT('',(37.6873684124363,15.1993281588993,5.05192769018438));
#413=CARTESIAN_POINT('',(37.8163304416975,15.1526040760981,4.48272058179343E-06));
#414=CARTESIAN_POINT('',(36.8142382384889,10.068252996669,5.04142115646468));
#415=CARTESIAN_POINT('',(38.6592594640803,14.8287186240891,5.15155756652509));
#416=CARTESIAN_POINT('',(38.9228408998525,14.730928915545,0.0506763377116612));
#417=CARTESIAN_POINT('',(38.6051869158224,9.23214063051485,5.20383148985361));
#418=CARTESIAN_POINT('',(40.5787065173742,14.0604614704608,5.44067467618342));
#419=CARTESIAN_POINT('',(41.1139607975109,13.854128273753,0.249375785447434));
#420=CARTESIAN_POINT('',(39.491703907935,8.79812364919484,5.32485383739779));
#421=CARTESIAN_POINT('',(41.5268531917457,13.6621370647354,5.63137069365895));
#422=CARTESIAN_POINT('',(42.1985619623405,13.3989904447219,0.39743947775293));
#423=CARTESIAN_POINT('',(41.2377536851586,7.90266378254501,5.64228458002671));
#424=CARTESIAN_POINT('',(43.3883290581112,12.8430887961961,6.09734068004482));
#425=CARTESIAN_POINT('',(44.3347507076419,12.4599542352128,0.785797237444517));
#426=CARTESIAN_POINT('',(42.0973517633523,7.44129663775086,5.83849231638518));
#427=CARTESIAN_POINT('',(44.302171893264,12.4217618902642,6.37367578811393));
#428=CARTESIAN_POINT('',(45.3864181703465,11.9761352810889,1.02584581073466));
#429=CARTESIAN_POINT('',(43.7858801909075,6.4934972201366,6.30199730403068));
#430=CARTESIAN_POINT('',(46.0907894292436,11.5593392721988,7.00575673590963));
#431=CARTESIAN_POINT('',(47.4522329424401,10.9822124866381,1.59291677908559));
#432=CARTESIAN_POINT('',(44.6148337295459,6.0070845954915,6.56923949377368));
#433=CARTESIAN_POINT('',(46.9657985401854,11.1176283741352,7.36279790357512));
#434=CARTESIAN_POINT('',(48.4664086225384,10.4721292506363,1.91987180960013));
#435=CARTESIAN_POINT('',(45.4260701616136,5.50948791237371,6.86999713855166));
#436=CARTESIAN_POINT('',(47.8116966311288,10.6709628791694,7.75420284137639));
#437=CARTESIAN_POINT('',(49.458908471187,9.95031770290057,2.28783101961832));
#438=(BOUNDED_SURFACE() B_SPLINE_SURFACE(3,2,((#264,#265,#266),(#267,#268,#269),(#270,#271,
#272),(#273,#274,#275),(#276,#277,#278),(#279,#280,#281),(#282,#283,#284),(#285,#286,#287),
(#288,#289,#290),(#291,#292,#293),(#294,#295,#296),(#297,#298,#299),(#300,#301,#302),(#303,#304,
#305),(#306,#307,#308),(#309,#310,#311),(#312,#313,#314),(#315,#316,#317),(#318,#319,#320),
(#321,#322,#323),(#324,#325,#326),(#327,#328,#329),(#330,#331,#332),(#333,#334,#335),(#336,#337,
#338),(#339,#340,#341),(#342,#343,#344),(#345,#346,#347),(#348,#349,#350),(#351,#352,#353),
(#354,#355,#356),(#357,#358,#359),(#360,#361,#362),(#363,#364,#365),(#366,#367,#368),(#369,#370,
#371),(#372,#373,#374),(#375,#376,#377),(#378,#379,#380),(#381,#382,#383),(#384,#385,#386),
(#387,#388,#389),(#390,#391,#392),(#393,#394,#395),(#396,#397,#398),(#399,#400,#401),(#402,#403,
#404),(#405,#406,#407),(#408,#409,#410),(#411,#412,#413),(#414,#415,#416),(#417,#418,#419),
(#420,#421,#422),(#423,#424,#425),(#426,#427,#428),(#429,#430,#431),(#432,#433,#434),(#435,#436,
#437)),.UNSPECIFIED.,.F.,.F.,.F.) B_SPLINE_SURFACE_WITH_KNOTS((4,2,2,2,2,2,2,2,2,2,2,2,2,2,2,2,
2,2,2,2,2,2,2,2,2,2,2,2,4),(3,3),(0.,3.3759280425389,6.75443063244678,10.1412704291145,
13.5268934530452,16.4163665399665,19.3054732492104,22.190543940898,25.0756239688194,
27.9722127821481,30.8688312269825,33.7661002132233,36.663219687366,39.4024819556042,
42.1416406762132,44.8802769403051,47.6188931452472,50.2773563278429,52.9357283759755,
55.5932635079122,58.2509429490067,61.1157387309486,63.9806894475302,66.8505415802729,
69.7207629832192,73.1066860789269,76.4938649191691,79.8720661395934,83.247656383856),(0.,1.),
.UNSPECIFIED.) GEOMETRIC_REPRESENTATION_ITEM() RATIONAL_B_SPLINE_SURFACE(((1.,0.655888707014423,
1.),(1.,0.66070212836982,1.),(1.,0.665393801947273,1.),(1.,0.674513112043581,1.),(1.,
0.678940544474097,1.),(1.,0.687513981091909,1.),(1.,0.691659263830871,1.),(1.,0.699629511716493,
1.),(1.,0.703454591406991,1.),(1.,0.710223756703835,1.),(1.,0.713214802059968,1.),(1.,
0.718928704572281,1.),(1.,0.721651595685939,1.),(1.,0.726809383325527,1.),(1.,0.729244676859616,
1.),(1.,0.733815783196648,1.),(1.,0.735951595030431,1.),(1.,0.739916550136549,1.),(1.,
0.741744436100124,1.),(1.,0.745069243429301,1.),(1.,0.746566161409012,1.),(1.,0.749217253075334,
1.),(1.,0.7503713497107,1.),(1.,0.752326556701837,1.),(1.,0.753127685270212,1.),(1.,
0.754336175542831,1.),(1.,0.754762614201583,1.),(1.,0.755290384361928,1.),(1.,0.755391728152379,
1.),(1.,0.755268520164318,1.),(1.,0.755044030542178,1.),(1.,0.75427107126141,1.),(1.,
0.753722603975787,1.),(1.,0.75232680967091,1.),(1.,0.751488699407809,1.),(1.,0.749517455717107,
1.),(1.,0.748384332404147,1.),(1.,0.745831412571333,1.),(1.,0.744411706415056,1.),(1.,
0.741294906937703,1.),(1.,0.739597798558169,1.),(1.,0.735794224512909,1.),(1.,0.733666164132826,
1.),(1.,0.729114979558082,1.),(1.,0.726691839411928,1.),(1.,0.721561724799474,1.),(1.,
0.718854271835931,1.),(1.,0.713174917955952,1.),(1.,0.71020298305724,1.),(1.,0.703454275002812,
1.),(1.,0.699628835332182,1.),(1.,0.691657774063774,1.),(1.,0.687512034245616,1.),(1.,
0.67893844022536,1.),(1.,0.674511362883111,1.),(1.,0.665392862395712,1.),(1.,0.660701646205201,
1.),(1.,0.655888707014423,1.))) REPRESENTATION_ITEM('') SURFACE());
#439=CARTESIAN_POINT('',(2.28783101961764,9.95031770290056,49.4589084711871));
#440=CARTESIAN_POINT('',(1.91983497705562,10.4721815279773,48.4663091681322));
#441=CARTESIAN_POINT('',(1.59285130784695,10.9823146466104,47.4520298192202));
#442=CARTESIAN_POINT('',(1.02574407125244,11.9763261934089,45.3860121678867));
#443=CARTESIAN_POINT('',(0.78568693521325,12.4601843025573,44.3342458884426));
#444=CARTESIAN_POINT('',(0.397366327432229,13.39920408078,42.198057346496));
#445=CARTESIAN_POINT('',(0.249330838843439,13.8542919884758,41.1135609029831));
#446=CARTESIAN_POINT('',(0.0506672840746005,14.7310034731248,38.922645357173));
#447=CARTESIAN_POINT('',(4.24193162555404E-06,15.1526390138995,37.8162342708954));
#448=CARTESIAN_POINT('',(-3.62029345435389E-06,15.900064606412,35.75332774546));
#449=CARTESIAN_POINT('',(0.0368917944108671,16.2308454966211,34.7986237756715));
#450=CARTESIAN_POINT('',(0.186476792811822,16.8635602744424,32.8856378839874));
#451=CARTESIAN_POINT('',(0.299156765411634,17.1654978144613,31.927356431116));
#452=CARTESIAN_POINT('',(0.601552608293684,17.7380768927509,30.0150467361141));
#453=CARTESIAN_POINT('',(0.791160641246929,18.0087615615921,29.061014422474));
#454=CARTESIAN_POINT('',(1.24817656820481,18.5173281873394,27.1628293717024));
#455=CARTESIAN_POINT('',(1.51558471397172,18.7552100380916,26.2186766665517));
#456=CARTESIAN_POINT('',(2.12939565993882,19.1971690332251,24.343866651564));
#457=CARTESIAN_POINT('',(2.47610932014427,19.4011075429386,23.4132781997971));
#458=CARTESIAN_POINT('',(3.24699135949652,19.7722965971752,21.5771395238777));
#459=CARTESIAN_POINT('',(3.67116053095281,19.9395467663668,20.6715895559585));
#460=CARTESIAN_POINT('',(4.59511080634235,20.2358966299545,18.8931146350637));
#461=CARTESIAN_POINT('',(5.09490887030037,20.3649877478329,18.0201970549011));
#462=CARTESIAN_POINT('',(6.16705088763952,20.5837598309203,16.314921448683));
#463=CARTESIAN_POINT('',(6.73939109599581,20.6734428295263,15.4825613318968));
#464=CARTESIAN_POINT('',(7.91950052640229,20.8087530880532,13.9098681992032));
#465=CARTESIAN_POINT('',(8.52364008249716,20.8565145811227,13.1669920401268));
#466=CARTESIAN_POINT('',(9.78893380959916,20.915627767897,11.7299598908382));
#467=CARTESIAN_POINT('',(10.4500858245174,20.9269808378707,11.0358020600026));
#468=CARTESIAN_POINT('',(11.8243432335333,20.9131797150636,9.70165307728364));
#469=CARTESIAN_POINT('',(12.537438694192,20.8880324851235,9.06165161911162));
#470=CARTESIAN_POINT('',(14.0101553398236,20.8014654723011,7.84033654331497));
#471=CARTESIAN_POINT('',(14.7697761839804,20.7400459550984,7.2590224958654));
#472=CARTESIAN_POINT('',(16.3066679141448,20.5837957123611,6.17511742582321));
#473=CARTESIAN_POINT('',(17.0827715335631,20.4899954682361,5.67072031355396));
#474=CARTESIAN_POINT('',(18.6673108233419,20.2694808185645,4.72378959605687));
#475=CARTESIAN_POINT('',(19.4757453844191,20.1427675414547,4.28125387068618));
#476=CARTESIAN_POINT('',(21.1187419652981,19.8574546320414,3.46027590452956));
#477=CARTESIAN_POINT('',(21.9532956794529,19.6988650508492,3.08181352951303));
#478=CARTESIAN_POINT('',(23.6428019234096,19.3509534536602,2.3901756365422));
#479=CARTESIAN_POINT('',(24.4977555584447,19.1616297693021,2.07700366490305));
#480=CARTESIAN_POINT('',(26.2893659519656,18.7376793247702,1.49480123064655));
#481=CARTESIAN_POINT('',(27.22719756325,18.5006718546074,1.23111275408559));
#482=CARTESIAN_POINT('',(29.1124922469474,17.9943426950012,0.780432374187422));
#483=CARTESIAN_POINT('',(30.0599558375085,17.7250192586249,0.593444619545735));
#484=CARTESIAN_POINT('',(31.9592918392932,17.1555301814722,0.295156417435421));
#485=CARTESIAN_POINT('',(32.9111690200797,16.8553125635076,0.183986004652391));
#486=CARTESIAN_POINT('',(34.811352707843,16.2264347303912,0.0364010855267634));
#487=CARTESIAN_POINT('',(35.7596587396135,15.8977708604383,-3.7999678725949E-06));
#488=CARTESIAN_POINT('',(37.8163304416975,15.1526040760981,4.48272058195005E-06));
#489=CARTESIAN_POINT('',(38.9228408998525,14.730928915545,0.0506763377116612));
#490=CARTESIAN_POINT('',(41.1139607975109,13.854128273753,0.249375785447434));
#491=CARTESIAN_POINT('',(42.1985619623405,13.3989904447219,0.39743947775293));
#492=CARTESIAN_POINT('',(44.3347507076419,12.4599542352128,0.785797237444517));
#493=CARTESIAN_POINT('',(45.3864181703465,11.9761352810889,1.02584581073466));
#494=CARTESIAN_POINT('',(47.4522329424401,10.9822124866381,1.59291677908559));
#495=CARTESIAN_POINT('',(48.4664086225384,10.4721292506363,1.91987180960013));
#496=CARTESIAN_POINT('',(49.458908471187,9.95031770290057,2.28783101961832));
#497=B_SPLINE_CURVE_WITH_KNOTS('',3,(#439,#440,#441,#442,#443,#444,#445,#446,#447,#448,#449,
#450,#451,#452,#453,#454,#455,#456,#457,#458,#459,#460,#461,#462,#463,#464,#465,#466,#467,#468,
#469,#470,#471,#472,#473,#474,#475,#476,#477,#478,#479,#480,#481,#482,#483,#484,#485,#486,#487,
#488,#489,#490,#491,#492,#493,#494,#495,#496),.UNSPECIFIED.,.F.,.F.,(4,2,2,2,2,2,2,2,2,2,2,2,2,
2,2,2,2,2,2,2,2,2,2,2,2,2,2,2,4),(0.,3.3759280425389,6.75443063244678,10.1412704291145,
13.5268934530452,16.4163665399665,19.3054732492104,22.190543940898,25.0756239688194,
27.9722127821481,30.8688312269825,33.7661002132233,36.663219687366,39.4024819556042,
42.1416406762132,44.8802769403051,47.6188931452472,50.2773563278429,52.9357283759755,
55.5932635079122,58.2509429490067,61.1157387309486,63.9806894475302,66.8505415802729,
69.7207629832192,73.1066860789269,76.4938649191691,79.8720661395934,83.247656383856),.UNSPECIFIED.);
#498=CARTESIAN_POINT('',(36.7032276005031,15.5558999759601,1.28148634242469E-13));
#499=VERTEX_POINT('',#498);
#500=EDGE_CURVE('E376',#261,#499,#497,.T.);
#501=ORIENTED_EDGE('',*,*,#500,.T.);
#502=CARTESIAN_POINT('',(45.4260701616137,5.50948791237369,-6.86999713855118));
#503=CARTESIAN_POINT('',(47.8116966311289,10.6709628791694,-7.75420284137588));
#504=CARTESIAN_POINT('',(49.4589084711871,9.95031770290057,-2.28783101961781));
#505=CARTESIAN_POINT('',(44.6147524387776,6.00713444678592,-6.56920938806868));
#506=CARTESIAN_POINT('',(46.9657144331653,11.1176727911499,-7.3627590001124));
#507=CARTESIAN_POINT('',(48.4663091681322,10.4721815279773,-1.91983497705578));
#508=CARTESIAN_POINT('',(43.7857141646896,6.49359463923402,-6.30194379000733));
#509=CARTESIAN_POINT('',(46.0906154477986,11.5594271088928,-7.00568573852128));
#510=CARTESIAN_POINT('',(47.4520298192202,10.9823146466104,-1.5928513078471));
#511=CARTESIAN_POINT('',(42.0970199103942,7.44147869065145,-5.83840915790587));
#512=CARTESIAN_POINT('',(44.3018208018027,12.4219272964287,-6.37356108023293));
#513=CARTESIAN_POINT('',(45.3860121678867,11.9763261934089,-1.02574407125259));
#514=CARTESIAN_POINT('',(41.2373410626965,7.90288317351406,-5.64219442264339));
#515=CARTESIAN_POINT('',(43.3878911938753,12.8432886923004,-6.0972131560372));
#516=CARTESIAN_POINT('',(44.3342458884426,12.4601843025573,-0.785686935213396));
#517=CARTESIAN_POINT('',(39.4912914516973,8.79832737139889,-5.32479404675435));
#518=CARTESIAN_POINT('',(41.5264112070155,13.6623243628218,-5.63127781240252));
#519=CARTESIAN_POINT('',(42.198057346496,13.39920408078,-0.397366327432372));
#520=CARTESIAN_POINT('',(38.6048600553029,9.23229674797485,-5.20379475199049));
#521=CARTESIAN_POINT('',(40.5783554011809,14.0606052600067,-5.44061351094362));
#522=CARTESIAN_POINT('',(41.1135609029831,13.8542919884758,-0.249330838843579));
#523=CARTESIAN_POINT('',(36.8140784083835,10.0683240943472,-5.04141375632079));
#524=CARTESIAN_POINT('',(38.6590868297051,14.8287845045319,-5.15153974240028));
#525=CARTESIAN_POINT('',(38.922645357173,14.7310034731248,-0.0506672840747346));
#526=CARTESIAN_POINT('',(35.9097347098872,10.4703934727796,-5.0000034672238));
#527=CARTESIAN_POINT('',(37.6872830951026,15.199359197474,-5.05192286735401));
#528=CARTESIAN_POINT('',(37.8162342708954,15.1526390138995,-4.2419317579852E-06));
#529=CARTESIAN_POINT('',(34.2235833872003,11.1831344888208,-4.99999704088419));
#530=CARTESIAN_POINT('',(35.8713862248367,15.8572908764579,-4.9561085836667));
#531=CARTESIAN_POINT('',(35.75332774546,15.900064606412,3.62029332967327E-06));
#532=CARTESIAN_POINT('',(33.4432400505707,11.4985653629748,-5.03015412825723));
#533=CARTESIAN_POINT('',(35.0300796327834,16.1489121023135,-4.94625745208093));
#534=CARTESIAN_POINT('',(34.7986237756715,16.2308454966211,-0.036891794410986));
#535=CARTESIAN_POINT('',(31.8796288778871,12.101918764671,-5.15241994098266));
#536=CARTESIAN_POINT('',(33.3428848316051,16.7070337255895,-4.99814861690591));
#537=CARTESIAN_POINT('',(32.8856378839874,16.8635602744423,-0.186476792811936));
#538=CARTESIAN_POINT('',(31.0963614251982,12.3898447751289,-5.24452081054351));
#539=CARTESIAN_POINT('',(32.4964091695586,16.9739426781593,-5.05933431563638));
#540=CARTESIAN_POINT('',(31.9273564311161,17.1654978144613,-0.29915676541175));
#541=CARTESIAN_POINT('',(29.5333029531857,12.9358530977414,-5.49168913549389));
#542=CARTESIAN_POINT('',(30.8064360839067,17.4802647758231,-5.2544694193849));
#543=CARTESIAN_POINT('',(30.0150467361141,17.7380768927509,-0.601552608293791));
#544=CARTESIAN_POINT('',(28.7535086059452,13.1939765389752,-5.64666844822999));
#545=CARTESIAN_POINT('',(29.9622746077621,17.7201016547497,-5.38787779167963));
#546=CARTESIAN_POINT('',(29.061014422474,18.0087615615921,-0.791160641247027));
#547=CARTESIAN_POINT('',(27.2019951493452,13.6789429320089,-6.02021809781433));
#548=CARTESIAN_POINT('',(28.2825655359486,18.1707634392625,-5.72802045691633));
#549=CARTESIAN_POINT('',(27.1628293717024,18.5173281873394,-1.2481765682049));
#550=CARTESIAN_POINT('',(26.4302760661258,13.9057857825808,-6.2387886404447));
#551=CARTESIAN_POINT('',(27.4462808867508,18.3819518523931,-5.9344379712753));
#552=CARTESIAN_POINT('',(26.2186766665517,18.7552100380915,-1.51558471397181));
#553=CARTESIAN_POINT('',(24.8978685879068,14.3272354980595,-6.74049733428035));
#554=CARTESIAN_POINT('',(25.7861773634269,18.7742802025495,-6.42141854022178));
#555=CARTESIAN_POINT('',(24.343866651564,19.1971690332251,-2.12939565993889));
#556=CARTESIAN_POINT('',(24.1372364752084,14.5217101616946,-7.02388957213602));
#557=CARTESIAN_POINT('',(24.9616091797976,18.9556349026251,-6.70209323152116));
#558=CARTESIAN_POINT('',(23.4132781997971,19.4011075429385,-2.47610932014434));
#559=CARTESIAN_POINT('',(22.6364376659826,14.8756740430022,-7.65398296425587));
#560=CARTESIAN_POINT('',(23.3357727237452,19.2856272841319,-7.33617749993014));
#561=CARTESIAN_POINT('',(21.5771395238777,19.7722965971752,-3.24699135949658));
#562=CARTESIAN_POINT('',(21.8962711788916,15.0351629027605,-8.00068476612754));
#563=CARTESIAN_POINT('',(22.5336800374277,19.4345566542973,-7.68954504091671));
#564=CARTESIAN_POINT('',(20.6715895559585,19.9395467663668,-3.67116053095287));
#565=CARTESIAN_POINT('',(20.4426048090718,15.3177605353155,-8.75589105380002));
#566=CARTESIAN_POINT('',(20.9601065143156,19.6983233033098,-8.46710027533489));
#567=CARTESIAN_POINT('',(18.8931146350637,20.2358966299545,-4.59511080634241));
#568=CARTESIAN_POINT('',(19.7291109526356,15.4408611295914,-9.16440940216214));
#569=CARTESIAN_POINT('',(20.1878034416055,19.813394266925,-8.89140978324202));
#570=CARTESIAN_POINT('',(18.0201970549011,20.3649877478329,-5.09490887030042));
#571=CARTESIAN_POINT('',(18.3352752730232,15.6494810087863,-10.0407427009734));
#572=CARTESIAN_POINT('',(18.6813856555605,20.0082837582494,-9.80778859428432));
#573=CARTESIAN_POINT('',(16.314921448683,20.5837598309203,-6.16705088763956));
#574=CARTESIAN_POINT('',(17.654931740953,15.7350022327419,-10.5085545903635));
#575=CARTESIAN_POINT('',(17.9464641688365,20.0882869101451,-10.3001077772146));
#576=CARTESIAN_POINT('',(15.4825613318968,20.6734428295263,-6.73939109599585));
#577=CARTESIAN_POINT('',(16.3694645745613,15.8640333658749,-11.4731368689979));
#578=CARTESIAN_POINT('',(16.560621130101,20.2089045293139,-11.31996207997));
#579=CARTESIAN_POINT('',(13.9098681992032,20.8087530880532,-7.91950052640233));
#580=CARTESIAN_POINT('',(15.7622622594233,15.9095784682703,-11.9669404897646));
#581=CARTESIAN_POINT('',(15.9067072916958,20.2515259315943,-11.8444162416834));
#582=CARTESIAN_POINT('',(13.1669920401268,20.8565145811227,-8.52364008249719));
#583=CARTESIAN_POINT('',(14.5876798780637,15.9659484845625,-13.0011495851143));
#584=CARTESIAN_POINT('',(14.6448156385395,20.3042340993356,-12.9461876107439));
#585=CARTESIAN_POINT('',(11.7299598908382,20.915627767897,-9.78893380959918));
#586=CARTESIAN_POINT('',(14.0202983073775,15.9767747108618,-13.541553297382));
#587=CARTESIAN_POINT('',(14.0362609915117,20.3143675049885,-13.5239399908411));
#588=CARTESIAN_POINT('',(11.0358020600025,20.9269808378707,-10.4500858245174));
#589=CARTESIAN_POINT('',(12.9298092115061,15.9636140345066,-14.6648256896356));
#590=CARTESIAN_POINT('',(12.8702112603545,20.3020608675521,-14.7273860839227));
#591=CARTESIAN_POINT('',(9.70165307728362,20.9131797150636,-11.8243432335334));
#592=CARTESIAN_POINT('',(12.4066932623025,15.9396337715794,-15.2476862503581));
#593=CARTESIAN_POINT('',(12.3122116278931,20.2796164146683,-15.3535977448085));
#594=CARTESIAN_POINT('',(9.06165161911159,20.8880324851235,-12.537438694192));
#595=CARTESIAN_POINT('',(11.4084308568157,15.8570839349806,-16.4514359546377));
#596=CARTESIAN_POINT('',(11.2515126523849,20.2024357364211,-16.6486816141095));
#597=CARTESIAN_POINT('',(7.84033654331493,20.8014654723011,-14.0101553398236));
#598=CARTESIAN_POINT('',(10.933284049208,15.7985146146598,-17.0723248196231));
#599=CARTESIAN_POINT('',(10.7484136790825,20.1476334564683,-17.3181539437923));
#600=CARTESIAN_POINT('',(7.25902249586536,20.7400459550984,-14.7697761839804));
#601=CARTESIAN_POINT('',(10.0473360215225,15.6495152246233,-18.3285291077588));
#602=CARTESIAN_POINT('',(9.815056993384,20.0083863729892,-18.6737386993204));
#603=CARTESIAN_POINT('',(6.17511742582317,20.5837957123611,-16.3066679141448));
#604=CARTESIAN_POINT('',(9.63505856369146,15.5600678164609,-18.9628904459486));
#605=CARTESIAN_POINT('',(9.3828021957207,19.9247412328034,-19.3594343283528));
#606=CARTESIAN_POINT('',(5.67072031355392,20.4899954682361,-17.0827715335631));
#607=CARTESIAN_POINT('',(8.86106882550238,15.3497862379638,-20.2580402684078));
#608=CARTESIAN_POINT('',(8.57645584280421,19.7283409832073,-20.7599290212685));
#609=CARTESIAN_POINT('',(4.72378959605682,20.2694808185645,-18.6673108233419));
#610=CARTESIAN_POINT('',(8.49935481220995,15.2289531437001,-20.9188278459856));
#611=CARTESIAN_POINT('',(8.20219752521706,19.6154327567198,-21.4753559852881));
#612=CARTESIAN_POINT('',(4.28125387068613,20.1427675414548,-19.4757453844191));
#613=CARTESIAN_POINT('',(7.82831467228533,14.9568802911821,-22.2617587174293));
#614=CARTESIAN_POINT('',(7.51385404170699,19.3615408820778,-22.9293610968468));
#615=CARTESIAN_POINT('',(3.4602759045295,19.8574546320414,-21.1187419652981));
#616=CARTESIAN_POINT('',(7.51897208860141,14.8056501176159,-22.9438952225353));
#617=CARTESIAN_POINT('',(7.19969016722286,19.2203717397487,-23.6685731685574));
#618=CARTESIAN_POINT('',(3.08181352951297,19.6988650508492,-21.9532956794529));
#619=CARTESIAN_POINT('',(6.95365023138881,14.4738834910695,-24.324841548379));
#620=CARTESIAN_POINT('',(6.63258179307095,18.9111185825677,-25.164628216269));
#621=CARTESIAN_POINT('',(2.39017563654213,19.3509534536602,-23.6428019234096));
#622=CARTESIAN_POINT('',(6.69767385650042,14.2933454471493,-25.0236522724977));
#623=CARTESIAN_POINT('',(6.37968611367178,18.7428037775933,-25.9221071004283));
#624=CARTESIAN_POINT('',(2.07700366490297,19.1616297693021,-24.4977555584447));
#625=CARTESIAN_POINT('',(6.22180091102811,13.8890685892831,-26.4880551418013));
#626=CARTESIAN_POINT('',(5.91827932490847,18.3664012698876,-27.5088463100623));
#627=CARTESIAN_POINT('',(1.49480123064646,18.7376793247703,-26.2893659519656));
#628=CARTESIAN_POINT('',(6.006270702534,13.6630595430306,-27.2546075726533));
#629=CARTESIAN_POINT('',(5.71503754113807,18.1560011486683,-28.3395120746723));
#630=CARTESIAN_POINT('',(1.2311127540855,18.5006718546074,-27.22719756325));
#631=CARTESIAN_POINT('',(5.63789951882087,13.1802267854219,-28.7955848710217));
#632=CARTESIAN_POINT('',(5.38021584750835,17.7073398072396,-30.0077810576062));
#633=CARTESIAN_POINT('',(0.780432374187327,17.9943426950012,-29.1124922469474));
#634=CARTESIAN_POINT('',(5.48506193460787,12.9234014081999,-29.5700101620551));
#635=CARTESIAN_POINT('',(5.24895287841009,17.4687206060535,-30.8461047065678));
#636=CARTESIAN_POINT('',(0.593444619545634,17.7250192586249,-30.0599558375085));
#637=CARTESIAN_POINT('',(5.24125105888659,12.3803396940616,-31.1224643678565));
#638=CARTESIAN_POINT('',(5.05706521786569,16.9651457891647,-32.5245765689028));
#639=CARTESIAN_POINT('',(0.295156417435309,17.1555301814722,-31.9592918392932));
#640=CARTESIAN_POINT('',(5.15038405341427,12.0940537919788,-31.9004971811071));
#641=CARTESIAN_POINT('',(4.99699511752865,16.6997669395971,-33.3653727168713));
#642=CARTESIAN_POINT('',(0.183986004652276,16.8553125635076,-32.9111690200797));
#643=CARTESIAN_POINT('',(5.02975303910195,11.494359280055,-33.4536442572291));
#644=CARTESIAN_POINT('',(4.94638911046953,16.1450398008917,-35.0412500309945));
#645=CARTESIAN_POINT('',(0.0364010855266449,16.2264347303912,-34.8113527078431));
#646=CARTESIAN_POINT('',(4.99999689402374,11.1809471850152,-34.2287581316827));
#647=CARTESIAN_POINT('',(4.95639957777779,15.8552909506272,-35.8769063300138));
#648=CARTESIAN_POINT('',(-3.79996799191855E-06,15.8977708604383,-35.7596587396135));
#649=CARTESIAN_POINT('',(5.00000366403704,10.4703601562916,-35.909813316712));
#650=CARTESIAN_POINT('',(5.05192769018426,15.1993281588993,-37.6873684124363));
#651=CARTESIAN_POINT('',(4.48272045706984E-06,15.1526040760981,-37.8163304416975));
#652=CARTESIAN_POINT('',(5.04142115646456,10.068252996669,-36.8142382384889));
#653=CARTESIAN_POINT('',(5.15155756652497,14.8287186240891,-38.6592594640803));
#654=CARTESIAN_POINT('',(0.0506763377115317,14.730928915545,-38.9228408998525));
#655=CARTESIAN_POINT('',(5.20383148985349,9.23214063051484,-38.6051869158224));
#656=CARTESIAN_POINT('',(5.44067467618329,14.0604614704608,-40.5787065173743));
#657=CARTESIAN_POINT('',(0.249375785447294,13.854128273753,-41.1139607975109));
#658=CARTESIAN_POINT('',(5.32485383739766,8.7981236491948,-39.4917039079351));
#659=CARTESIAN_POINT('',(5.63137069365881,13.6621370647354,-41.5268531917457));
#660=CARTESIAN_POINT('',(0.397439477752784,13.3989904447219,-42.1985619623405));
#661=CARTESIAN_POINT('',(5.64228458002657,7.90266378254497,-41.2377536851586));
#662=CARTESIAN_POINT('',(6.09734068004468,12.8430887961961,-43.3883290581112));
#663=CARTESIAN_POINT('',(0.785797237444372,12.4599542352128,-44.3347507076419));
#664=CARTESIAN_POINT('',(5.83849231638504,7.44129663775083,-42.0973517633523));
#665=CARTESIAN_POINT('',(6.3736757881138,12.4217618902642,-44.302171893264));
#666=CARTESIAN_POINT('',(1.02584581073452,11.9761352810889,-45.3864181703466));
#667=CARTESIAN_POINT('',(6.30199730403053,6.49349722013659,-43.7858801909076));
#668=CARTESIAN_POINT('',(7.00575673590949,11.5593392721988,-46.0907894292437));
#669=CARTESIAN_POINT('',(1.59291677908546,10.9822124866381,-47.4522329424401));
#670=CARTESIAN_POINT('',(6.56923949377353,6.00708459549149,-44.614833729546));
#671=CARTESIAN_POINT('',(7.36279790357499,11.1176283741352,-46.9657985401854));
#672=CARTESIAN_POINT('',(1.91987180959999,10.4721292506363,-48.4664086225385));
#673=CARTESIAN_POINT('',(6.8699971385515,5.50948791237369,-45.4260701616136));
#674=CARTESIAN_POINT('',(7.75420284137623,10.6709628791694,-47.8116966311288));
#675=CARTESIAN_POINT('',(2.28783101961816,9.95031770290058,-49.4589084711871));
#676=(BOUNDED_SURFACE() B_SPLINE_SURFACE(3,2,((#502,#503,#504),(#505,#506,#507),(#508,#509,
#510),(#511,#512,#513),(#514,#515,#516),(#517,#518,#519),(#520,#521,#522),(#523,#524,#525),
(#526,#527,#528),(#529,#530,#531),(#532,#533,#534),(#535,#536,#537),(#538,#539,#540),(#541,#542,
#543),(#544,#545,#546),(#547,#548,#549),(#550,#551,#552),(#553,#554,#555),(#556,#557,#558),
(#559,#560,#561),(#562,#563,#564),(#565,#566,#567),(#568,#569,#570),(#571,#572,#573),(#574,#575,
#576),(#577,#578,#579),(#580,#581,#582),(#583,#584,#585),(#586,#587,#588),(#589,#590,#591),
(#592,#593,#594),(#595,#596,#597),(#598,#599,#600),(#601,#602,#603),(#604,#605,#606),(#607,#608,
#609),(#610,#611,#612),(#613,#614,#615),(#616,#617,#618),(#619,#620,#621),(#622,#623,#624),
(#625,#626,#627),(#628,#629,#630),(#631,#632,#633),(#634,#635,#636),(#637,#638,#639),(#640,#641,
#642),(#643,#644,#645),(#646,#647,#648),(#649,#650,#651),(#652,#653,#654),(#655,#656,#657),
(#658,#659,#660),(#661,#662,#663),(#664,#665,#666),(#667,#668,#669),(#670,#671,#672),(#673,#674,
#675)),.UNSPECIFIED.,.F.,.F.,.F.) B_SPLINE_SURFACE_WITH_KNOTS((4,2,2,2,2,2,2,2,2,2,2,2,2,2,2,2,
2,2,2,2,2,2,2,2,2,2,2,2,4),(3,3),(0.,3.3759280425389,6.75443063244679,10.1412704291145,
13.5268934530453,16.4163665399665,19.3054732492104,22.190543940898,25.0756239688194,
27.9722127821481,30.8688312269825,33.7661002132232,36.663219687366,39.4024819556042,
42.1416406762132,44.8802769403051,47.6188931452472,50.2773563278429,52.9357283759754,
55.5932635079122,58.2509429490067,61.1157387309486,63.9806894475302,66.8505415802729,
69.7207629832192,73.1066860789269,76.4938649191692,79.8720661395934,83.2476563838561),(0.,1.),
.UNSPECIFIED.) GEOMETRIC_REPRESENTATION_ITEM() RATIONAL_B_SPLINE_SURFACE(((1.,0.655888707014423,
1.),(1.,0.660702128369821,1.),(1.,0.665393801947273,1.),(1.,0.674513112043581,1.),(1.,
0.678940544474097,1.),(1.,0.687513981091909,1.),(1.,0.691659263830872,1.),(1.,0.699629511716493,
1.),(1.,0.703454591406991,1.),(1.,0.710223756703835,1.),(1.,0.713214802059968,1.),(1.,
0.718928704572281,1.),(1.,0.721651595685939,1.),(1.,0.726809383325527,1.),(1.,0.729244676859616,
1.),(1.,0.733815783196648,1.),(1.,0.735951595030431,1.),(1.,0.739916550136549,1.),(1.,
0.741744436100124,1.),(1.,0.745069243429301,1.),(1.,0.746566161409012,1.),(1.,0.749217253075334,
1.),(1.,0.7503713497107,1.),(1.,0.752326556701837,1.),(1.,0.753127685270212,1.),(1.,
0.754336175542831,1.),(1.,0.754762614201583,1.),(1.,0.755290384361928,1.),(1.,0.755391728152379,
1.),(1.,0.755268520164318,1.),(1.,0.755044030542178,1.),(1.,0.75427107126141,1.),(1.,
0.753722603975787,1.),(1.,0.75232680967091,1.),(1.,0.751488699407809,1.),(1.,0.749517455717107,
1.),(1.,0.748384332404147,1.),(1.,0.745831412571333,1.),(1.,0.744411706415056,1.),(1.,
0.741294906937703,1.),(1.,0.739597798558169,1.),(1.,0.735794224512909,1.),(1.,0.733666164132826,
1.),(1.,0.729114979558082,1.),(1.,0.726691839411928,1.),(1.,0.721561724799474,1.),(1.,
0.718854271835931,1.),(1.,0.713174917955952,1.),(1.,0.71020298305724,1.),(1.,0.703454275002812,
1.),(1.,0.699628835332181,1.),(1.,0.691657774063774,1.),(1.,0.687512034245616,1.),(1.,
0.67893844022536,1.),(1.,0.674511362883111,1.),(1.,0.665392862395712,1.),(1.,0.660701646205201,
1.),(1.,0.655888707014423,1.))) REPRESENTATION_ITEM('') SURFACE());
#677=CARTESIAN_POINT('',(49.4589084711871,9.95031770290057,-2.28783101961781));
#678=CARTESIAN_POINT('',(48.4663091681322,10.4721815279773,-1.91983497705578));
#679=CARTESIAN_POINT('',(47.4520298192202,10.9823146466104,-1.5928513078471));
#680=CARTESIAN_POINT('',(45.3860121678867,11.9763261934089,-1.02574407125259));
#681=CARTESIAN_POINT('',(44.3342458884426,12.4601843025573,-0.785686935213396));
#682=CARTESIAN_POINT('',(42.198057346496,13.39920408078,-0.397366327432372));
#683=CARTESIAN_POINT('',(41.1135609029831,13.8542919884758,-0.249330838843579));
#684=CARTESIAN_POINT('',(38.922645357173,14.7310034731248,-0.0506672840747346));
#685=CARTESIAN_POINT('',(37.8162342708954,15.1526390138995,-4.2419317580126E-06));
#686=CARTESIAN_POINT('',(35.75332774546,15.900064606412,3.62029332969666E-06));
#687=CARTESIAN_POINT('',(34.7986237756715,16.2308454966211,-0.036891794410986));
#688=CARTESIAN_POINT('',(32.8856378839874,16.8635602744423,-0.186476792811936));
#689=CARTESIAN_POINT('',(31.9273564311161,17.1654978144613,-0.29915676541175));
#690=CARTESIAN_POINT('',(30.0150467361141,17.7380768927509,-0.601552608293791));
#691=CARTESIAN_POINT('',(29.061014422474,18.0087615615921,-0.791160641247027));
#692=CARTESIAN_POINT('',(27.1628293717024,18.5173281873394,-1.2481765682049));
#693=CARTESIAN_POINT('',(26.2186766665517,18.7552100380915,-1.51558471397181));
#694=CARTESIAN_POINT('',(24.343866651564,19.1971690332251,-2.12939565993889));
#695=CARTESIAN_POINT('',(23.4132781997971,19.4011075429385,-2.47610932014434));
#696=CARTESIAN_POINT('',(21.5771395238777,19.7722965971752,-3.24699135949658));
#697=CARTESIAN_POINT('',(20.6715895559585,19.9395467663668,-3.67116053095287));
#698=CARTESIAN_POINT('',(18.8931146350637,20.2358966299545,-4.59511080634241));
#699=CARTESIAN_POINT('',(18.0201970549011,20.3649877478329,-5.09490887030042));
#700=CARTESIAN_POINT('',(16.314921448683,20.5837598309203,-6.16705088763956));
#701=CARTESIAN_POINT('',(15.4825613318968,20.6734428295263,-6.73939109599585));
#702=CARTESIAN_POINT('',(13.9098681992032,20.8087530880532,-7.91950052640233));
#703=CARTESIAN_POINT('',(13.1669920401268,20.8565145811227,-8.52364008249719));
#704=CARTESIAN_POINT('',(11.7299598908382,20.915627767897,-9.78893380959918));
#705=CARTESIAN_POINT('',(11.0358020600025,20.9269808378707,-10.4500858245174));
#706=CARTESIAN_POINT('',(9.70165307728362,20.9131797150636,-11.8243432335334));
#707=CARTESIAN_POINT('',(9.06165161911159,20.8880324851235,-12.537438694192));
#708=CARTESIAN_POINT('',(7.84033654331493,20.8014654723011,-14.0101553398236));
#709=CARTESIAN_POINT('',(7.25902249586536,20.7400459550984,-14.7697761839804));
#710=CARTESIAN_POINT('',(6.17511742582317,20.5837957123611,-16.3066679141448));
#711=CARTESIAN_POINT('',(5.67072031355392,20.4899954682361,-17.0827715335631));
#712=CARTESIAN_POINT('',(4.72378959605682,20.2694808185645,-18.6673108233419));
#713=CARTESIAN_POINT('',(4.28125387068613,20.1427675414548,-19.4757453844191));
#714=CARTESIAN_POINT('',(3.46027590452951,19.8574546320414,-21.1187419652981));
#715=CARTESIAN_POINT('',(3.08181352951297,19.6988650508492,-21.9532956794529));
#716=CARTESIAN_POINT('',(2.39017563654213,19.3509534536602,-23.6428019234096));
#717=CARTESIAN_POINT('',(2.07700366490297,19.1616297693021,-24.4977555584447));
#718=CARTESIAN_POINT('',(1.49480123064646,18.7376793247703,-26.2893659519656));
#719=CARTESIAN_POINT('',(1.2311127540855,18.5006718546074,-27.22719756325));
#720=CARTESIAN_POINT('',(0.780432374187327,17.9943426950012,-29.1124922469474));
#721=CARTESIAN_POINT('',(0.593444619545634,17.7250192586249,-30.0599558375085));
#722=CARTESIAN_POINT('',(0.295156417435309,17.1555301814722,-31.9592918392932));
#723=CARTESIAN_POINT('',(0.183986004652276,16.8553125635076,-32.9111690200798));
#724=CARTESIAN_POINT('',(0.0364010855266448,16.2264347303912,-34.8113527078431));
#725=CARTESIAN_POINT('',(-3.79996799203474E-06,15.8977708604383,-35.7596587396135));
#726=CARTESIAN_POINT('',(4.48272045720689E-06,15.1526040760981,-37.8163304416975));
#727=CARTESIAN_POINT('',(0.0506763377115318,14.730928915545,-38.9228408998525));
#728=CARTESIAN_POINT('',(0.249375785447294,13.854128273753,-41.1139607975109));
#729=CARTESIAN_POINT('',(0.397439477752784,13.3989904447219,-42.1985619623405));
#730=CARTESIAN_POINT('',(0.785797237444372,12.4599542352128,-44.3347507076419));
#731=CARTESIAN_POINT('',(1.02584581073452,11.9761352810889,-45.3864181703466));
#732=CARTESIAN_POINT('',(1.59291677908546,10.9822124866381,-47.4522329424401));
#733=CARTESIAN_POINT('',(1.91987180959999,10.4721292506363,-48.4664086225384));
#734=CARTESIAN_POINT('',(2.28783101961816,9.95031770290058,-49.4589084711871));
#735=B_SPLINE_CURVE_WITH_KNOTS('',3,(#677,#678,#679,#680,#681,#682,#683,#684,#685,#686,#687,
#688,#689,#690,#691,#692,#693,#694,#695,#696,#697,#698,#699,#700,#701,#702,#703,#704,#705,#706,
#707,#708,#709,#710,#711,#712,#713,#714,#715,#716,#717,#718,#719,#720,#721,#722,#723,#724,#725,
#726,#727,#728,#729,#730,#731,#732,#733,#734),.UNSPECIFIED.,.F.,.F.,(4,2,2,2,2,2,2,2,2,2,2,2,2,
2,2,2,2,2,2,2,2,2,2,2,2,2,2,2,4),(0.,3.3759280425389,6.75443063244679,10.1412704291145,
13.5268934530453,16.4163665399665,19.3054732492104,22.190543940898,25.0756239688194,
27.9722127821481,30.8688312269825,33.7661002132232,36.663219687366,39.4024819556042,
42.1416406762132,44.8802769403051,47.6188931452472,50.2773563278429,52.9357283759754,
55.5932635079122,58.2509429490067,61.1157387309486,63.9806894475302,66.8505415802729,
69.7207629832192,73.1066860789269,76.4938649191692,79.8720661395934,83.2476563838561),.UNSPECIFIED.);
#736=CARTESIAN_POINT('',(0.,15.5558999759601,-36.7032276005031));
#737=VERTEX_POINT('',#736);
#738=EDGE_CURVE('E69',#499,#737,#735,.T.);
#739=ORIENTED_EDGE('',*,*,#738,.T.);
#740=CARTESIAN_POINT('',(-6.86999713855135,5.5094879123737,-45.4260701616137));
#741=CARTESIAN_POINT('',(-7.75420284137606,10.6709628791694,-47.8116966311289));
#742=CARTESIAN_POINT('',(-2.28783101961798,9.95031770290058,-49.4589084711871));
#743=CARTESIAN_POINT('',(-6.56920938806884,6.00713444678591,-44.6147524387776));
#744=CARTESIAN_POINT('',(-7.36275900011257,11.1176727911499,-46.9657144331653));
#745=CARTESIAN_POINT('',(-1.91983497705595,10.4721815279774,-48.4663091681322));
#746=CARTESIAN_POINT('',(-6.30194379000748,6.49359463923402,-43.7857141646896));
#747=CARTESIAN_POINT('',(-7.00568573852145,11.5594271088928,-46.0906154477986));
#748=CARTESIAN_POINT('',(-1.59285130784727,10.9823146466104,-47.4520298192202));
#749=CARTESIAN_POINT('',(-5.83840915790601,7.44147869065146,-42.0970199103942));
#750=CARTESIAN_POINT('',(-6.37356108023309,12.4219272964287,-44.3018208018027));
#751=CARTESIAN_POINT('',(-1.02574407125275,11.9763261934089,-45.3860121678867));
#752=CARTESIAN_POINT('',(-5.64219442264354,7.90288317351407,-41.2373410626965));
#753=CARTESIAN_POINT('',(-6.09721315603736,12.8432886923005,-43.3878911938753));
#754=CARTESIAN_POINT('',(-0.785686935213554,12.4601843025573,-44.3342458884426));
#755=CARTESIAN_POINT('',(-5.3247940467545,8.7983273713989,-39.4912914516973));
#756=CARTESIAN_POINT('',(-5.63127781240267,13.6623243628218,-41.5264112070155));
#757=CARTESIAN_POINT('',(-0.397366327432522,13.39920408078,-42.198057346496));
#758=CARTESIAN_POINT('',(-5.20379475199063,9.23229674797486,-38.6048600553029));
#759=CARTESIAN_POINT('',(-5.44061351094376,14.0606052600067,-40.5783554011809));
#760=CARTESIAN_POINT('',(-0.249330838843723,13.8542919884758,-41.1135609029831));
#761=CARTESIAN_POINT('',(-5.04141375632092,10.0683240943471,-36.8140784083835));
#762=CARTESIAN_POINT('',(-5.15153974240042,14.8287845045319,-38.6590868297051));
#763=CARTESIAN_POINT('',(-0.0506672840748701,14.7310034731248,-38.922645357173));
#764=CARTESIAN_POINT('',(-5.00000346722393,10.4703934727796,-35.9097347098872));
#765=CARTESIAN_POINT('',(-5.05192286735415,15.199359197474,-37.6872830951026));
#766=CARTESIAN_POINT('',(-4.24193188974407E-06,15.1526390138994,-37.8162342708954));
#767=CARTESIAN_POINT('',(-4.99999704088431,11.1831344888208,-34.2235833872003));
#768=CARTESIAN_POINT('',(-4.95610858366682,15.8572908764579,-35.8713862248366));
#769=CARTESIAN_POINT('',(3.62029320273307E-06,15.900064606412,-35.75332774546));
#770=CARTESIAN_POINT('',(-5.03015412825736,11.4985653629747,-33.4432400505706));
#771=CARTESIAN_POINT('',(-4.94625745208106,16.1489121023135,-35.0300796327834));
#772=CARTESIAN_POINT('',(-0.0368917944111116,16.2308454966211,-34.7986237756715));
#773=CARTESIAN_POINT('',(-5.15241994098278,12.101918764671,-31.8796288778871));
#774=CARTESIAN_POINT('',(-4.99814861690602,16.7070337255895,-33.342884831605));
#775=CARTESIAN_POINT('',(-0.186476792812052,16.8635602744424,-32.8856378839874));
#776=CARTESIAN_POINT('',(-5.24452081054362,12.3898447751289,-31.0963614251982));
#777=CARTESIAN_POINT('',(-5.05933431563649,16.9739426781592,-32.4964091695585));
#778=CARTESIAN_POINT('',(-0.299156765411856,17.1654978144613,-31.9273564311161));
#779=CARTESIAN_POINT('',(-5.491689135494,12.9358530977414,-29.5333029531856));
#780=CARTESIAN_POINT('',(-5.25446941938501,17.4802647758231,-30.8064360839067));
#781=CARTESIAN_POINT('',(-0.601552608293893,17.7380768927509,-30.0150467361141));
#782=CARTESIAN_POINT('',(-5.6466684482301,13.1939765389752,-28.7535086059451));
#783=CARTESIAN_POINT('',(-5.38787779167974,17.7201016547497,-29.9622746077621));
#784=CARTESIAN_POINT('',(-0.791160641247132,18.0087615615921,-29.061014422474));
#785=CARTESIAN_POINT('',(-6.02021809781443,13.6789429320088,-27.2019951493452));
#786=CARTESIAN_POINT('',(-5.72802045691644,18.1707634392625,-28.2825655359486));
#787=CARTESIAN_POINT('',(-1.248176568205,18.5173281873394,-27.1628293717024));
#788=CARTESIAN_POINT('',(-6.2387886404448,13.9057857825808,-26.4302760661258));
#789=CARTESIAN_POINT('',(-5.9344379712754,18.381951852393,-27.4462808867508));
#790=CARTESIAN_POINT('',(-1.51558471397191,18.7552100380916,-26.2186766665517));
#791=CARTESIAN_POINT('',(-6.74049733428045,14.3272354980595,-24.8978685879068));
#792=CARTESIAN_POINT('',(-6.42141854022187,18.7742802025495,-25.7861773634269));
#793=CARTESIAN_POINT('',(-2.12939565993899,19.1971690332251,-24.3438666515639));
#794=CARTESIAN_POINT('',(-7.02388957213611,14.5217101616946,-24.1372364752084));
#795=CARTESIAN_POINT('',(-6.70209323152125,18.9556349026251,-24.9616091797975));
#796=CARTESIAN_POINT('',(-2.47610932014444,19.4011075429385,-23.4132781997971));
#797=CARTESIAN_POINT('',(-7.65398296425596,14.8756740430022,-22.6364376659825));
#798=CARTESIAN_POINT('',(-7.33617749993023,19.2856272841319,-23.3357727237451));
#799=CARTESIAN_POINT('',(-3.24699135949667,19.7722965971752,-21.5771395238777));
#800=CARTESIAN_POINT('',(-8.00068476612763,15.0351629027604,-21.8962711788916));
#801=CARTESIAN_POINT('',(-7.6895450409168,19.4345566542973,-22.5336800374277));
#802=CARTESIAN_POINT('',(-3.67116053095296,19.9395467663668,-20.6715895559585));
#803=CARTESIAN_POINT('',(-8.7558910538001,15.3177605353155,-20.4426048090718));
#804=CARTESIAN_POINT('',(-8.46710027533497,19.6983233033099,-20.9601065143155));
#805=CARTESIAN_POINT('',(-4.59511080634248,20.2358966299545,-18.8931146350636));
#806=CARTESIAN_POINT('',(-9.16440940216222,15.4408611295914,-19.7291109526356));
#807=CARTESIAN_POINT('',(-8.8914097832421,19.813394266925,-20.1878034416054));
#808=CARTESIAN_POINT('',(-5.09490887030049,20.3649877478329,-18.0201970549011));
#809=CARTESIAN_POINT('',(-10.0407427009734,15.6494810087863,-18.3352752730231));
#810=CARTESIAN_POINT('',(-9.80778859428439,20.0082837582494,-18.6813856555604));
#811=CARTESIAN_POINT('',(-6.16705088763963,20.5837598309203,-16.314921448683));
#812=CARTESIAN_POINT('',(-10.5085545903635,15.7350022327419,-17.6549317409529));
#813=CARTESIAN_POINT('',(-10.3001077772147,20.0882869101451,-17.9464641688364));
#814=CARTESIAN_POINT('',(-6.73939109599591,20.6734428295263,-15.4825613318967));
#815=CARTESIAN_POINT('',(-11.473136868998,15.8640333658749,-16.3694645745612));
#816=CARTESIAN_POINT('',(-11.3199620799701,20.2089045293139,-16.5606211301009));
#817=CARTESIAN_POINT('',(-7.91950052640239,20.8087530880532,-13.9098681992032));
#818=CARTESIAN_POINT('',(-11.9669404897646,15.9095784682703,-15.7622622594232));
#819=CARTESIAN_POINT('',(-11.8444162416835,20.2515259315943,-15.9067072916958));
#820=CARTESIAN_POINT('',(-8.52364008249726,20.8565145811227,-13.1669920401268));
#821=CARTESIAN_POINT('',(-13.0011495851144,15.9659484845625,-14.5876798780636));
#822=CARTESIAN_POINT('',(-12.946187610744,20.3042340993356,-14.6448156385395));
#823=CARTESIAN_POINT('',(-9.78893380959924,20.915627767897,-11.7299598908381));
#824=CARTESIAN_POINT('',(-13.541553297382,15.9767747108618,-14.0202983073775));
#825=CARTESIAN_POINT('',(-13.5239399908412,20.3143675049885,-14.0362609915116));
#826=CARTESIAN_POINT('',(-10.4500858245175,20.9269808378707,-11.0358020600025));
#827=CARTESIAN_POINT('',(-14.6648256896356,15.9636140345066,-12.9298092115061));
#828=CARTESIAN_POINT('',(-14.7273860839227,20.3020608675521,-12.8702112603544));
#829=CARTESIAN_POINT('',(-11.8243432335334,20.9131797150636,-9.70165307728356));
#830=CARTESIAN_POINT('',(-15.2476862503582,15.9396337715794,-12.4066932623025));
#831=CARTESIAN_POINT('',(-15.3535977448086,20.2796164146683,-12.312211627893));
#832=CARTESIAN_POINT('',(-12.537438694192,20.8880324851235,-9.06165161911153));
#833=CARTESIAN_POINT('',(-16.4514359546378,15.8570839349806,-11.4084308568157));
#834=CARTESIAN_POINT('',(-16.6486816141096,20.2024357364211,-11.2515126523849));
#835=CARTESIAN_POINT('',(-14.0101553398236,20.8014654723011,-7.84033654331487));
#836=CARTESIAN_POINT('',(-17.0723248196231,15.7985146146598,-10.9332840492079));
#837=CARTESIAN_POINT('',(-17.3181539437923,20.1476334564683,-10.7484136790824));
#838=CARTESIAN_POINT('',(-14.7697761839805,20.7400459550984,-7.2590224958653));
#839=CARTESIAN_POINT('',(-18.3285291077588,15.6495152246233,-10.0473360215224));
#840=CARTESIAN_POINT('',(-18.6737386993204,20.0083863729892,-9.81505699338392));
#841=CARTESIAN_POINT('',(-16.3066679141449,20.5837957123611,-6.1751174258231));
#842=CARTESIAN_POINT('',(-18.9628904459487,15.5600678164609,-9.63505856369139));
#843=CARTESIAN_POINT('',(-19.3594343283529,19.9247412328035,-9.38280219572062));
#844=CARTESIAN_POINT('',(-17.0827715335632,20.4899954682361,-5.67072031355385));
#845=CARTESIAN_POINT('',(-20.2580402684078,15.3497862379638,-8.8610688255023));
#846=CARTESIAN_POINT('',(-20.7599290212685,19.7283409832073,-8.57645584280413));
#847=CARTESIAN_POINT('',(-18.667310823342,20.2694808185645,-4.72378959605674));
#848=CARTESIAN_POINT('',(-20.9188278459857,15.2289531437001,-8.49935481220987));
#849=CARTESIAN_POINT('',(-21.4753559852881,19.6154327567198,-8.20219752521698));
#850=CARTESIAN_POINT('',(-19.4757453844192,20.1427675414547,-4.28125387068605));
#851=CARTESIAN_POINT('',(-22.2617587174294,14.9568802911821,-7.82831467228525));
#852=CARTESIAN_POINT('',(-22.9293610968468,19.3615408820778,-7.5138540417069));
#853=CARTESIAN_POINT('',(-21.1187419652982,19.8574546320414,-3.46027590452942));
#854=CARTESIAN_POINT('',(-22.9438952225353,14.8056501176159,-7.51897208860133));
#855=CARTESIAN_POINT('',(-23.6685731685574,19.2203717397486,-7.19969016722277));
#856=CARTESIAN_POINT('',(-21.9532956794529,19.6988650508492,-3.08181352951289));
#857=CARTESIAN_POINT('',(-24.324841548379,14.4738834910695,-6.95365023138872));
#858=CARTESIAN_POINT('',(-25.1646282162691,18.9111185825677,-6.63258179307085));
#859=CARTESIAN_POINT('',(-23.6428019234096,19.3509534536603,-2.39017563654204));
#860=CARTESIAN_POINT('',(-25.0236522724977,14.2933454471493,-6.69767385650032));
#861=CARTESIAN_POINT('',(-25.9221071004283,18.7428037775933,-6.37968611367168));
#862=CARTESIAN_POINT('',(-24.4977555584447,19.1616297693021,-2.07700366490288));
#863=CARTESIAN_POINT('',(-26.4880551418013,13.8890685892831,-6.22180091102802));
#864=CARTESIAN_POINT('',(-27.5088463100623,18.3664012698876,-5.91827932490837));
#865=CARTESIAN_POINT('',(-26.2893659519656,18.7376793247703,-1.49480123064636));
#866=CARTESIAN_POINT('',(-27.2546075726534,13.6630595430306,-6.00627070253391));
#867=CARTESIAN_POINT('',(-28.3395120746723,18.1560011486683,-5.71503754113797));
#868=CARTESIAN_POINT('',(-27.22719756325,18.5006718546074,-1.2311127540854));
#869=CARTESIAN_POINT('',(-28.7955848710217,13.1802267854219,-5.63789951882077));
#870=CARTESIAN_POINT('',(-30.0077810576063,17.7073398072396,-5.38021584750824));
#871=CARTESIAN_POINT('',(-29.1124922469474,17.9943426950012,-0.780432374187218));
#872=CARTESIAN_POINT('',(-29.5700101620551,12.9234014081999,-5.48506193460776));
#873=CARTESIAN_POINT('',(-30.8461047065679,17.4687206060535,-5.24895287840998));
#874=CARTESIAN_POINT('',(-30.0599558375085,17.7250192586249,-0.593444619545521));
#875=CARTESIAN_POINT('',(-31.1224643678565,12.3803396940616,-5.24125105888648));
#876=CARTESIAN_POINT('',(-32.5245765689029,16.9651457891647,-5.05706521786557));
#877=CARTESIAN_POINT('',(-31.9592918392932,17.1555301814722,-0.29515641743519));
#878=CARTESIAN_POINT('',(-31.9004971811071,12.0940537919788,-5.15038405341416));
#879=CARTESIAN_POINT('',(-33.3653727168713,16.6997669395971,-4.99699511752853));
#880=CARTESIAN_POINT('',(-32.9111690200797,16.8553125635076,-0.183986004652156));
#881=CARTESIAN_POINT('',(-33.4536442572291,11.494359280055,-5.02975303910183));
#882=CARTESIAN_POINT('',(-35.0412500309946,16.1450398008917,-4.94638911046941));
#883=CARTESIAN_POINT('',(-34.8113527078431,16.2264347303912,-0.0364010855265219));
#884=CARTESIAN_POINT('',(-34.2287581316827,11.1809471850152,-4.99999689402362));
#885=CARTESIAN_POINT('',(-35.8769063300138,15.8552909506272,-4.95639957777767));
#886=CARTESIAN_POINT('',(-35.7596587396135,15.8977708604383,3.79996811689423E-06));
#887=CARTESIAN_POINT('',(-35.909813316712,10.4703601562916,-5.00000366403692));
#888=CARTESIAN_POINT('',(-37.6873684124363,15.1993281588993,-5.05192769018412));
#889=CARTESIAN_POINT('',(-37.8163304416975,15.1526040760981,-4.48272032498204E-06));
#890=CARTESIAN_POINT('',(-36.8142382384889,10.068252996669,-5.04142115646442));
#891=CARTESIAN_POINT('',(-38.6592594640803,14.8287186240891,-5.15155756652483));
#892=CARTESIAN_POINT('',(-38.9228408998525,14.730928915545,-0.050676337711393));
#893=CARTESIAN_POINT('',(-38.6051869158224,9.23214063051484,-5.20383148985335));
#894=CARTESIAN_POINT('',(-40.5787065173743,14.0604614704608,-5.44067467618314));
#895=CARTESIAN_POINT('',(-41.1139607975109,13.854128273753,-0.249375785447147));
#896=CARTESIAN_POINT('',(-39.4917039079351,8.79812364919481,-5.32485383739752));
#897=CARTESIAN_POINT('',(-41.5268531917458,13.6621370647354,-5.63137069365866));
#898=CARTESIAN_POINT('',(-42.1985619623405,13.3989904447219,-0.397439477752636));
#899=CARTESIAN_POINT('',(-41.2377536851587,7.90266378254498,-5.64228458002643));
#900=CARTESIAN_POINT('',(-43.3883290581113,12.8430887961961,-6.09734068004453));
#901=CARTESIAN_POINT('',(-44.3347507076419,12.4599542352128,-0.78579723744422));
#902=CARTESIAN_POINT('',(-42.0973517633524,7.44129663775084,-5.83849231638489));
#903=CARTESIAN_POINT('',(-44.302171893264,12.4217618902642,-6.37367578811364));
#904=CARTESIAN_POINT('',(-45.3864181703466,11.9761352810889,-1.02584581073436));
#905=CARTESIAN_POINT('',(-43.7858801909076,6.49349722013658,-6.30199730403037));
#906=CARTESIAN_POINT('',(-46.0907894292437,11.5593392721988,-7.00575673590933));
#907=CARTESIAN_POINT('',(-47.4522329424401,10.9822124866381,-1.59291677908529));
#908=CARTESIAN_POINT('',(-44.614833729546,6.00708459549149,-6.56923949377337));
#909=CARTESIAN_POINT('',(-46.9657985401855,11.1176283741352,-7.36279790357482));
#910=CARTESIAN_POINT('',(-48.4664086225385,10.4721292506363,-1.91987180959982));
#911=CARTESIAN_POINT('',(-45.4260701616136,5.50948791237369,-6.86999713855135));
#912=CARTESIAN_POINT('',(-47.8116966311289,10.6709628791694,-7.75420284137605));
#913=CARTESIAN_POINT('',(-49.4589084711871,9.95031770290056,-2.28783101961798));
#914=(BOUNDED_SURFACE() B_SPLINE_SURFACE(3,2,((#740,#741,#742),(#743,#744,#745),(#746,#747,
#748),(#749,#750,#751),(#752,#753,#754),(#755,#756,#757),(#758,#759,#760),(#761,#762,#763),
(#764,#765,#766),(#767,#768,#769),(#770,#771,#772),(#773,#774,#775),(#776,#777,#778),(#779,#780,
#781),(#782,#783,#784),(#785,#786,#787),(#788,#789,#790),(#791,#792,#793),(#794,#795,#796),
(#797,#798,#799),(#800,#801,#802),(#803,#804,#805),(#806,#807,#808),(#809,#810,#811),(#812,#813,
#814),(#815,#816,#817),(#818,#819,#820),(#821,#822,#823),(#824,#825,#826),(#827,#828,#829),
(#830,#831,#832),(#833,#834,#835),(#836,#837,#838),(#839,#840,#841),(#842,#843,#844),(#845,#846,
#847),(#848,#849,#850),(#851,#852,#853),(#854,#855,#856),(#857,#858,#859),(#860,#861,#862),
(#863,#864,#865),(#866,#867,#868),(#869,#870,#871),(#872,#873,#874),(#875,#876,#877),(#878,#879,
#880),(#881,#882,#883),(#884,#885,#886),(#887,#888,#889),(#890,#891,#892),(#893,#894,#895),
(#896,#897,#898),(#899,#900,#901),(#902,#903,#904),(#905,#906,#907),(#908,#909,#910),(#911,#912,
#913)),.UNSPECIFIED.,.F.,.F.,.F.) B_SPLINE_SURFACE_WITH_KNOTS((4,2,2,2,2,2,2,2,2,2,2,2,2,2,2,2,
2,2,2,2,2,2,2,2,2,2,2,2,4),(3,3),(0.,3.3759280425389,6.75443063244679,10.1412704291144,
13.5268934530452,16.4163665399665,19.3054732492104,22.190543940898,25.0756239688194,
27.9722127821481,30.8688312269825,33.7661002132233,36.663219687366,39.4024819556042,
42.1416406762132,44.8802769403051,47.6188931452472,50.2773563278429,52.9357283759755,
55.5932635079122,58.2509429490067,61.1157387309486,63.9806894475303,66.8505415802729,
69.7207629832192,73.1066860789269,76.4938649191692,79.8720661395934,83.2476563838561),(0.,1.),
.UNSPECIFIED.) GEOMETRIC_REPRESENTATION_ITEM() RATIONAL_B_SPLINE_SURFACE(((1.,0.655888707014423,
1.),(1.,0.660702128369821,1.),(1.,0.665393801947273,1.),(1.,0.674513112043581,1.),(1.,
0.678940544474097,1.),(1.,0.687513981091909,1.),(1.,0.691659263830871,1.),(1.,0.699629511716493,
1.),(1.,0.703454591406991,1.),(1.,0.710223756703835,1.),(1.,0.713214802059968,1.),(1.,
0.718928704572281,1.),(1.,0.721651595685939,1.),(1.,0.726809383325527,1.),(1.,0.729244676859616,
1.),(1.,0.733815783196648,1.),(1.,0.735951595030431,1.),(1.,0.739916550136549,1.),(1.,
0.741744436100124,1.),(1.,0.745069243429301,1.),(1.,0.746566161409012,1.),(1.,0.749217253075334,
1.),(1.,0.7503713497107,1.),(1.,0.752326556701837,1.),(1.,0.753127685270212,1.),(1.,
0.754336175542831,1.),(1.,0.754762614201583,1.),(1.,0.755290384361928,1.),(1.,0.755391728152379,
1.),(1.,0.755268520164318,1.),(1.,0.755044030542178,1.),(1.,0.75427107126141,1.),(1.,
0.753722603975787,1.),(1.,0.75232680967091,1.),(1.,0.751488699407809,1.),(1.,0.749517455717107,
1.),(1.,0.748384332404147,1.),(1.,0.745831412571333,1.),(1.,0.744411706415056,1.),(1.,
0.741294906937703,1.),(1.,0.739597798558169,1.),(1.,0.735794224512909,1.),(1.,0.733666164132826,
1.),(1.,0.729114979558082,1.),(1.,0.726691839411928,1.),(1.,0.721561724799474,1.),(1.,
0.718854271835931,1.),(1.,0.713174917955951,1.),(1.,0.71020298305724,1.),(1.,0.703454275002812,
1.),(1.,0.699628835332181,1.),(1.,0.691657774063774,1.),(1.,0.687512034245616,1.),(1.,
0.67893844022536,1.),(1.,0.674511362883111,1.),(1.,0.665392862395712,1.),(1.,0.660701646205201,
1.),(1.,0.655888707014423,1.))) REPRESENTATION_ITEM('') SURFACE());
#915=CARTESIAN_POINT('',(-2.28783101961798,9.95031770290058,-49.4589084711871));
#916=CARTESIAN_POINT('',(-1.91983497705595,10.4721815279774,-48.4663091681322));
#917=CARTESIAN_POINT('',(-1.59285130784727,10.9823146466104,-47.4520298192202));
#918=CARTESIAN_POINT('',(-1.02574407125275,11.9763261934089,-45.3860121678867));
#919=CARTESIAN_POINT('',(-0.785686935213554,12.4601843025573,-44.3342458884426));
#920=CARTESIAN_POINT('',(-0.397366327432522,13.39920408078,-42.198057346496));
#921=CARTESIAN_POINT('',(-0.249330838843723,13.8542919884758,-41.1135609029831));
#922=CARTESIAN_POINT('',(-0.0506672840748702,14.7310034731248,-38.922645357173));
#923=CARTESIAN_POINT('',(-4.24193188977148E-06,15.1526390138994,-37.8162342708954));
#924=CARTESIAN_POINT('',(3.62029320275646E-06,15.900064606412,-35.75332774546));
#925=CARTESIAN_POINT('',(-0.0368917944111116,16.2308454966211,-34.7986237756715));
#926=CARTESIAN_POINT('',(-0.186476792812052,16.8635602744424,-32.8856378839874));
#927=CARTESIAN_POINT('',(-0.299156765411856,17.1654978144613,-31.927356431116));
#928=CARTESIAN_POINT('',(-0.601552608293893,17.7380768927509,-30.0150467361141));
#929=CARTESIAN_POINT('',(-0.791160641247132,18.0087615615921,-29.061014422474));
#930=CARTESIAN_POINT('',(-1.248176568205,18.5173281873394,-27.1628293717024));
#931=CARTESIAN_POINT('',(-1.51558471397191,18.7552100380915,-26.2186766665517));
#932=CARTESIAN_POINT('',(-2.12939565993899,19.1971690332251,-24.3438666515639));
#933=CARTESIAN_POINT('',(-2.47610932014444,19.4011075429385,-23.4132781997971));
#934=CARTESIAN_POINT('',(-3.24699135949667,19.7722965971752,-21.5771395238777));
#935=CARTESIAN_POINT('',(-3.67116053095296,19.9395467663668,-20.6715895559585));
#936=CARTESIAN_POINT('',(-4.59511080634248,20.2358966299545,-18.8931146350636));
#937=CARTESIAN_POINT('',(-5.09490887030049,20.3649877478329,-18.0201970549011));
#938=CARTESIAN_POINT('',(-6.16705088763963,20.5837598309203,-16.314921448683));
#939=CARTESIAN_POINT('',(-6.73939109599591,20.6734428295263,-15.4825613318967));
#940=CARTESIAN_POINT('',(-7.91950052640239,20.8087530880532,-13.9098681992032));
#941=CARTESIAN_POINT('',(-8.52364008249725,20.8565145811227,-13.1669920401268));
#942=CARTESIAN_POINT('',(-9.78893380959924,20.915627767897,-11.7299598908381));
#943=CARTESIAN_POINT('',(-10.4500858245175,20.9269808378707,-11.0358020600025));
#944=CARTESIAN_POINT('',(-11.8243432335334,20.9131797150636,-9.70165307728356));
#945=CARTESIAN_POINT('',(-12.537438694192,20.8880324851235,-9.06165161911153));
#946=CARTESIAN_POINT('',(-14.0101553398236,20.8014654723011,-7.84033654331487));
#947=CARTESIAN_POINT('',(-14.7697761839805,20.7400459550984,-7.2590224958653));
#948=CARTESIAN_POINT('',(-16.3066679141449,20.5837957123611,-6.1751174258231));
#949=CARTESIAN_POINT('',(-17.0827715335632,20.4899954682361,-5.67072031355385));
#950=CARTESIAN_POINT('',(-18.6673108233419,20.2694808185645,-4.72378959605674));
#951=CARTESIAN_POINT('',(-19.4757453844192,20.1427675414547,-4.28125387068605));
#952=CARTESIAN_POINT('',(-21.1187419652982,19.8574546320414,-3.46027590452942));
#953=CARTESIAN_POINT('',(-21.9532956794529,19.6988650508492,-3.08181352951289));
#954=CARTESIAN_POINT('',(-23.6428019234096,19.3509534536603,-2.39017563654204));
#955=CARTESIAN_POINT('',(-24.4977555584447,19.1616297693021,-2.07700366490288));
#956=CARTESIAN_POINT('',(-26.2893659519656,18.7376793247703,-1.49480123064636));
#957=CARTESIAN_POINT('',(-27.22719756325,18.5006718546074,-1.2311127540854));
#958=CARTESIAN_POINT('',(-29.1124922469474,17.9943426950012,-0.780432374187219));
#959=CARTESIAN_POINT('',(-30.0599558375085,17.7250192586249,-0.593444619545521));
#960=CARTESIAN_POINT('',(-31.9592918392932,17.1555301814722,-0.29515641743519));
#961=CARTESIAN_POINT('',(-32.9111690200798,16.8553125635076,-0.183986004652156));
#962=CARTESIAN_POINT('',(-34.8113527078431,16.2264347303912,-0.0364010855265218));
#963=CARTESIAN_POINT('',(-35.7596587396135,15.8977708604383,3.7999681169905E-06));
#964=CARTESIAN_POINT('',(-37.8163304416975,15.1526040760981,-4.48272032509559E-06));
#965=CARTESIAN_POINT('',(-38.9228408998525,14.730928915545,-0.050676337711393));
#966=CARTESIAN_POINT('',(-41.1139607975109,13.854128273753,-0.249375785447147));
#967=CARTESIAN_POINT('',(-42.1985619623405,13.3989904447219,-0.397439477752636));
#968=CARTESIAN_POINT('',(-44.3347507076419,12.4599542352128,-0.78579723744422));
#969=CARTESIAN_POINT('',(-45.3864181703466,11.9761352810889,-1.02584581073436));
#970=CARTESIAN_POINT('',(-47.4522329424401,10.9822124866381,-1.59291677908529));
#971=CARTESIAN_POINT('',(-48.4664086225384,10.4721292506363,-1.91987180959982));
#972=CARTESIAN_POINT('',(-49.4589084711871,9.95031770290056,-2.28783101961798));
#973=B_SPLINE_CURVE_WITH_KNOTS('',3,(#915,#916,#917,#918,#919,#920,#921,#922,#923,#924,#925,
#926,#927,#928,#929,#930,#931,#932,#933,#934,#935,#936,#937,#938,#939,#940,#941,#942,#943,#944,
#945,#946,#947,#948,#949,#950,#951,#952,#953,#954,#955,#956,#957,#958,#959,#960,#961,#962,#963,
#964,#965,#966,#967,#968,#969,#970,#971,#972),.UNSPECIFIED.,.F.,.F.,(4,2,2,2,2,2,2,2,2,2,2,2,2,
2,2,2,2,2,2,2,2,2,2,2,2,2,2,2,4),(0.,3.3759280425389,6.75443063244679,10.1412704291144,
13.5268934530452,16.4163665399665,19.3054732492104,22.190543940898,25.0756239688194,
27.9722127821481,30.8688312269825,33.7661002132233,36.663219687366,39.4024819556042,
42.1416406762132,44.8802769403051,47.6188931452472,50.2773563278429,52.9357283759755,
55.5932635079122,58.2509429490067,61.1157387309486,63.9806894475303,66.8505415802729,
69.7207629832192,73.1066860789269,76.4938649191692,79.8720661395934,83.2476563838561),.UNSPECIFIED.);
#974=EDGE_CURVE('E358',#737,#259,#973,.T.);
#975=ORIENTED_EDGE('',*,*,#974,.T.);
#976=EDGE_LOOP('',(#263,#501,#739,#975));
#977=FACE_BOUND('',#976,.T.);
#978=ADVANCED_FACE('F39',(#977),#23,.T.);
#979=CARTESIAN_POINT('',(0.,0.,0.));
#980=DIRECTION('',(0.,1.,0.));
#981=DIRECTION('',(0.,0.,1.));
#982=AXIS2_PLACEMENT_3D('',#979,#980,#981);
#983=PLANE('',#982);
#984=CARTESIAN_POINT('',(35.0000000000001,0.,-34.9999999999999));
#985=DIRECTION('',(0.,1.,0.));
#986=DIRECTION('',(0.,0.,1.));
#987=AXIS2_PLACEMENT_3D('',#984,#985,#986);
#988=CIRCLE('',#987,35.);
#989=CARTESIAN_POINT('',(0.,0.,-35.));
#990=VERTEX_POINT('',#989);
#991=CARTESIAN_POINT('',(35.,0.,1.2220184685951E-13));
#992=VERTEX_POINT('',#991);
#993=EDGE_CURVE('E212',#990,#992,#988,.T.);
#994=ORIENTED_EDGE('',*,*,#993,.T.);
#995=CARTESIAN_POINT('',(34.9999999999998,0.,35.0000000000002));
#996=DIRECTION('',(0.,1.,0.));
#997=DIRECTION('',(0.,0.,1.));
#998=AXIS2_PLACEMENT_3D('',#995,#996,#997);
#999=CIRCLE('',#998,35.);
#1000=CARTESIAN_POINT('',(-3.69303783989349E-13,0.,35.));
#1001=VERTEX_POINT('',#1000);
#1002=EDGE_CURVE('E215',#992,#1001,#999,.T.);
#1003=ORIENTED_EDGE('',*,*,#1002,.T.);
#1004=CARTESIAN_POINT('',(-35.0000000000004,0.,34.9999999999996));
#1005=DIRECTION('',(0.,1.,0.));
#1006=DIRECTION('',(0.,0.,1.));
#1007=AXIS2_PLACEMENT_3D('',#1004,#1005,#1006);
#1008=CIRCLE('',#1007,35.);
#1009=CARTESIAN_POINT('',(-35.,0.,-3.67565504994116E-13));
#1010=VERTEX_POINT('',#1009);
#1011=EDGE_CURVE('E206',#1001,#1010,#1008,.T.);
#1012=ORIENTED_EDGE('',*,*,#1011,.T.);
#1013=CARTESIAN_POINT('',(-35.,0.,-35.));
#1014=DIRECTION('',(0.,1.,0.));
#1015=DIRECTION('',(0.,0.,1.));
#1016=AXIS2_PLACEMENT_3D('',#1013,#1014,#1015);
#1017=CIRCLE('',#1016,35.);
#1018=EDGE_CURVE('E209',#1010,#990,#1017,.T.);
#1019=ORIENTED_EDGE('',*,*,#1018,.T.);
#1020=EDGE_LOOP('',(#994,#1003,#1012,#1019));
#1021=FACE_BOUND('',#1020,.T.);
#1022=CARTESIAN_POINT('',(0.,0.,0.));
#1023=DIRECTION('',(0.,1.,0.));
#1024=DIRECTION('',(0.,0.,1.));
#1025=AXIS2_PLACEMENT_3D('',#1022,#1023,#1024);
#1026=CIRCLE('',#1025,13.9674178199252);
#1027=CARTESIAN_POINT('',(0.,0.,13.9674178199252));
#1028=VERTEX_POINT('',#1027);
#1029=EDGE_CURVE('E190',#1028,#1028,#1026,.T.);
#1030=ORIENTED_EDGE('',*,*,#1029,.T.);
#1031=EDGE_LOOP('',(#1030));
#1032=FACE_BOUND('',#1031,.T.);
#1033=ADVANCED_FACE('F473',(#1021,#1032),#983,.F.);
#1034=CARTESIAN_POINT('',(0.,-28.,0.));
#1035=DIRECTION('',(0.,1.,0.));
#1036=DIRECTION('',(0.,0.,1.));
#1037=AXIS2_PLACEMENT_3D('',#1034,#1035,#1036);
#1038=CONICAL_SURFACE('',#1037,12.5,0.05235987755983);
#1039=CARTESIAN_POINT('',(0.,-28.,0.));
#1040=DIRECTION('',(0.,1.,0.));
#1041=DIRECTION('',(0.,0.,1.));
#1042=AXIS2_PLACEMENT_3D('',#1039,#1040,#1041);
#1043=CIRCLE('',#1042,12.5);
#1044=CARTESIAN_POINT('',(0.,-28.,12.5));
#1045=VERTEX_POINT('',#1044);
#1046=EDGE_CURVE('E191',#1045,#1045,#1043,.T.);
#1047=ORIENTED_EDGE('',*,*,#1046,.T.);
#1048=EDGE_LOOP('',(#1047));
#1049=FACE_BOUND('',#1048,.T.);
#1050=ORIENTED_EDGE('',*,*,#1029,.F.);
#1051=EDGE_LOOP('',(#1050));
#1052=FACE_BOUND('',#1051,.T.);
#1053=ADVANCED_FACE('F477',(#1049,#1052),#1038,.T.);
#1054=CARTESIAN_POINT('',(0.,-28.,0.));
#1055=DIRECTION('',(0.,1.,0.));
#1056=DIRECTION('',(0.,0.,1.));
#1057=AXIS2_PLACEMENT_3D('',#1054,#1055,#1056);
#1058=PLANE('',#1057);
#1059=CARTESIAN_POINT('',(0.,-28.,0.));
#1060=DIRECTION('',(0.,-1.,0.));
#1061=DIRECTION('',(0.,0.,-1.));
#1062=AXIS2_PLACEMENT_3D('',#1059,#1060,#1061);
#1063=CIRCLE('',#1062,8.);
#1064=CARTESIAN_POINT('',(0.,-28.,-8.));
#1065=VERTEX_POINT('',#1064);
#1066=EDGE_CURVE('E148',#1065,#1065,#1063,.T.);
#1067=ORIENTED_EDGE('',*,*,#1066,.F.);
#1068=EDGE_LOOP('',(#1067));
#1069=FACE_BOUND('',#1068,.T.);
#1070=ORIENTED_EDGE('',*,*,#1046,.F.);
#1071=EDGE_LOOP('',(#1070));
#1072=FACE_BOUND('',#1071,.T.);
#1073=ADVANCED_FACE('F554',(#1069,#1072),#1058,.F.);
#1074=CARTESIAN_POINT('',(-35.,22.,0.));
#1075=DIRECTION('',(0.,-1.,0.));
#1076=DIRECTION('',(0.,0.,-1.));
#1077=AXIS2_PLACEMENT_3D('',#1074,#1075,#1076);
#1078=CYLINDRICAL_SURFACE('',#1077,5.);
#1079=DIRECTION('',(0.,-1.,0.));
#1080=VECTOR('',#1079,1.);
#1081=CARTESIAN_POINT('',(-35.,22.,-5.));
#1082=LINE('',#1081,#1080);
#1083=CARTESIAN_POINT('',(-35.,10.8549409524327,-5.));
#1084=VERTEX_POINT('',#1083);
#1085=CARTESIAN_POINT('',(-35.,5.00000000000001,-5.));
#1086=VERTEX_POINT('',#1085);
#1087=EDGE_CURVE('E186',#1084,#1086,#1082,.T.);
#1088=ORIENTED_EDGE('',*,*,#1087,.T.);
#1089=CARTESIAN_POINT('',(-35.,5.,0.));
#1090=DIRECTION('',(0.,-1.,0.));
#1091=DIRECTION('',(0.,0.,-1.));
#1092=AXIS2_PLACEMENT_3D('',#1089,#1090,#1091);
#1093=CIRCLE('',#1092,5.);
#1094=CARTESIAN_POINT('',(-35.0000000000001,5.00000000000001,4.99999999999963));
#1095=VERTEX_POINT('',#1094);
#1096=EDGE_CURVE('E349',#1086,#1095,#1093,.F.);
#1097=ORIENTED_EDGE('',*,*,#1096,.T.);
#1098=DIRECTION('',(0.,-1.,0.));
#1099=VECTOR('',#1098,1.);
#1100=CARTESIAN_POINT('',(-35.0000000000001,22.,4.99999999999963));
#1101=LINE('',#1100,#1099);
#1102=CARTESIAN_POINT('',(-35.0000000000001,10.8549409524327,4.99999999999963));
#1103=VERTEX_POINT('',#1102);
#1104=EDGE_CURVE('E161',#1103,#1095,#1101,.T.);
#1105=ORIENTED_EDGE('',*,*,#1104,.F.);
#1106=CARTESIAN_POINT('',(-35.,10.8549409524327,0.));
#1107=DIRECTION('',(0.,-1.,0.));
#1108=DIRECTION('',(0.,0.,-1.));
#1109=AXIS2_PLACEMENT_3D('',#1106,#1107,#1108);
#1110=CIRCLE('',#1109,5.);
#1111=EDGE_CURVE('E346',#1103,#1084,#1110,.T.);
#1112=ORIENTED_EDGE('',*,*,#1111,.T.);
#1113=EDGE_LOOP('',(#1088,#1097,#1105,#1112));
#1114=FACE_BOUND('',#1113,.T.);
#1115=ADVANCED_FACE('F526',(#1114),#1078,.T.);
#1116=CARTESIAN_POINT('',(-35.,22.,-35.));
#1117=DIRECTION('',(0.,-1.,0.));
#1118=DIRECTION('',(0.,0.,-1.));
#1119=AXIS2_PLACEMENT_3D('',#1116,#1117,#1118);
#1120=CYLINDRICAL_SURFACE('',#1119,30.);
#1121=DIRECTION('',(0.,-1.,0.));
#1122=VECTOR('',#1121,1.);
#1123=CARTESIAN_POINT('',(-5.,22.,-35.));
#1124=LINE('',#1123,#1122);
#1125=CARTESIAN_POINT('',(-5.,10.8549409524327,-35.));
#1126=VERTEX_POINT('',#1125);
#1127=CARTESIAN_POINT('',(-5.,5.00000000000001,-35.));
#1128=VERTEX_POINT('',#1127);
#1129=EDGE_CURVE('E182',#1126,#1128,#1124,.T.);
#1130=ORIENTED_EDGE('',*,*,#1129,.T.);
#1131=CARTESIAN_POINT('',(-35.,5.,-35.));
#1132=DIRECTION('',(0.,1.,0.));
#1133=DIRECTION('',(0.,0.,1.));
#1134=AXIS2_PLACEMENT_3D('',#1131,#1132,#1133);
#1135=CIRCLE('',#1134,30.);
#1136=EDGE_CURVE('E342',#1128,#1086,#1135,.F.);
#1137=ORIENTED_EDGE('',*,*,#1136,.T.);
#1138=ORIENTED_EDGE('',*,*,#1087,.F.);
#1139=CARTESIAN_POINT('',(-45.4260701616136,5.50948791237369,-6.86999713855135));
#1140=CARTESIAN_POINT('',(-44.614833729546,6.00708459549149,-6.56923949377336));
#1141=CARTESIAN_POINT('',(-43.7858801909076,6.49349722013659,-6.30199730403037));
#1142=CARTESIAN_POINT('',(-42.0973517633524,7.44129663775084,-5.83849231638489));
#1143=CARTESIAN_POINT('',(-41.2377536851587,7.90266378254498,-5.64228458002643));
#1144=CARTESIAN_POINT('',(-39.4917039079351,8.79812364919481,-5.32485383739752));
#1145=CARTESIAN_POINT('',(-38.6051869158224,9.23214063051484,-5.20383148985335));
#1146=CARTESIAN_POINT('',(-36.8142382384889,10.068252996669,-5.04142115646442));
#1147=CARTESIAN_POINT('',(-35.909813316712,10.4703601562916,-5.00000366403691));
#1148=CARTESIAN_POINT('',(-34.2287581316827,11.1809471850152,-4.99999689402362));
#1149=CARTESIAN_POINT('',(-33.4536442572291,11.494359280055,-5.02975303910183));
#1150=CARTESIAN_POINT('',(-31.9004971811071,12.0940537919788,-5.15038405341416));
#1151=CARTESIAN_POINT('',(-31.1224643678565,12.3803396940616,-5.24125105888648));
#1152=CARTESIAN_POINT('',(-29.5700101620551,12.9234014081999,-5.48506193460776));
#1153=CARTESIAN_POINT('',(-28.7955848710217,13.1802267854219,-5.63789951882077));
#1154=CARTESIAN_POINT('',(-27.2546075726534,13.6630595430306,-6.00627070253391));
#1155=CARTESIAN_POINT('',(-26.4880551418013,13.8890685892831,-6.22180091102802));
#1156=CARTESIAN_POINT('',(-25.0236522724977,14.2933454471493,-6.69767385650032));
#1157=CARTESIAN_POINT('',(-24.324841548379,14.4738834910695,-6.95365023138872));
#1158=CARTESIAN_POINT('',(-22.9438952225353,14.8056501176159,-7.51897208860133));
#1159=CARTESIAN_POINT('',(-22.2617587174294,14.9568802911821,-7.82831467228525));
#1160=CARTESIAN_POINT('',(-20.9188278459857,15.2289531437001,-8.49935481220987));
#1161=CARTESIAN_POINT('',(-20.2580402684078,15.3497862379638,-8.8610688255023));
#1162=CARTESIAN_POINT('',(-18.9628904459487,15.5600678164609,-9.63505856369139));
#1163=CARTESIAN_POINT('',(-18.3285291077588,15.6495152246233,-10.0473360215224));
#1164=CARTESIAN_POINT('',(-17.0723248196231,15.7985146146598,-10.9332840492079));
#1165=CARTESIAN_POINT('',(-16.4514359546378,15.8570839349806,-11.4084308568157));
#1166=CARTESIAN_POINT('',(-15.2476862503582,15.9396337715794,-12.4066932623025));
#1167=CARTESIAN_POINT('',(-14.6648256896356,15.9636140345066,-12.9298092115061));
#1168=CARTESIAN_POINT('',(-13.541553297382,15.9767747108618,-14.0202983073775));
#1169=CARTESIAN_POINT('',(-13.0011495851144,15.9659484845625,-14.5876798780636));
#1170=CARTESIAN_POINT('',(-11.9669404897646,15.9095784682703,-15.7622622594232));
#1171=CARTESIAN_POINT('',(-11.473136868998,15.8640333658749,-16.3694645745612));
#1172=CARTESIAN_POINT('',(-10.5085545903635,15.7350022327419,-17.6549317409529));
#1173=CARTESIAN_POINT('',(-10.0407427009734,15.6494810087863,-18.3352752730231));
#1174=CARTESIAN_POINT('',(-9.16440940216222,15.4408611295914,-19.7291109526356));
#1175=CARTESIAN_POINT('',(-8.7558910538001,15.3177605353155,-20.4426048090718));
#1176=CARTESIAN_POINT('',(-8.00068476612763,15.0351629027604,-21.8962711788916));
#1177=CARTESIAN_POINT('',(-7.65398296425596,14.8756740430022,-22.6364376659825));
#1178=CARTESIAN_POINT('',(-7.02388957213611,14.5217101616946,-24.1372364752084));
#1179=CARTESIAN_POINT('',(-6.74049733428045,14.3272354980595,-24.8978685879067));
#1180=CARTESIAN_POINT('',(-6.2387886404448,13.9057857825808,-26.4302760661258));
#1181=CARTESIAN_POINT('',(-6.02021809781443,13.6789429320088,-27.2019951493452));
#1182=CARTESIAN_POINT('',(-5.6466684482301,13.1939765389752,-28.7535086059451));
#1183=CARTESIAN_POINT('',(-5.491689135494,12.9358530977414,-29.5333029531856));
#1184=CARTESIAN_POINT('',(-5.24452081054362,12.3898447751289,-31.0963614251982));
#1185=CARTESIAN_POINT('',(-5.15241994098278,12.101918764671,-31.8796288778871));
#1186=CARTESIAN_POINT('',(-5.03015412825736,11.4985653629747,-33.4432400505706));
#1187=CARTESIAN_POINT('',(-4.99999704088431,11.1831344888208,-34.2235833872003));
#1188=CARTESIAN_POINT('',(-5.00000346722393,10.4703934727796,-35.9097347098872));
#1189=CARTESIAN_POINT('',(-5.04141375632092,10.0683240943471,-36.8140784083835));
#1190=CARTESIAN_POINT('',(-5.20379475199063,9.23229674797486,-38.6048600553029));
#1191=CARTESIAN_POINT('',(-5.3247940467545,8.7983273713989,-39.4912914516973));
#1192=CARTESIAN_POINT('',(-5.64219442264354,7.90288317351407,-41.2373410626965));
#1193=CARTESIAN_POINT('',(-5.83840915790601,7.44147869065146,-42.0970199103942));
#1194=CARTESIAN_POINT('',(-6.30194379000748,6.49359463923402,-43.7857141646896));
#1195=CARTESIAN_POINT('',(-6.56920938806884,6.00713444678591,-44.6147524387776));
#1196=CARTESIAN_POINT('',(-6.86999713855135,5.5094879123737,-45.4260701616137));
#1197=B_SPLINE_CURVE_WITH_KNOTS('',3,(#1139,#1140,#1141,#1142,#1143,#1144,#1145,#1146,#1147,
#1148,#1149,#1150,#1151,#1152,#1153,#1154,#1155,#1156,#1157,#1158,#1159,#1160,#1161,#1162,#1163,
#1164,#1165,#1166,#1167,#1168,#1169,#1170,#1171,#1172,#1173,#1174,#1175,#1176,#1177,#1178,#1179,
#1180,#1181,#1182,#1183,#1184,#1185,#1186,#1187,#1188,#1189,#1190,#1191,#1192,#1193,#1194,#1195,
#1196),.UNSPECIFIED.,.F.,.F.,(4,2,2,2,2,2,2,2,2,2,2,2,2,2,2,2,2,2,2,2,2,2,2,2,2,2,2,2,4),(0.,
3.37559024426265,6.75379146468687,10.1409703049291,13.5268934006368,16.3971148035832,
19.2669669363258,22.1319176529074,24.9967134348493,27.6543928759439,30.3119280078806,
32.9703000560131,35.6287632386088,38.367379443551,41.1060157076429,43.8451744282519,
46.5844366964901,49.4815561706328,52.3788251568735,55.2754436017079,58.1720324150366,
61.0571124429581,63.9421831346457,66.8312898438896,69.7207629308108,73.1063859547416,
76.4932257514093,79.8717283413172,83.2476563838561),.UNSPECIFIED.);
#1198=EDGE_CURVE('E336',#1084,#1126,#1197,.T.);
#1199=ORIENTED_EDGE('',*,*,#1198,.T.);
#1200=EDGE_LOOP('',(#1130,#1137,#1138,#1199));
#1201=FACE_BOUND('',#1200,.T.);
#1202=ADVANCED_FACE('F293',(#1201),#1120,.F.);
#1203=CARTESIAN_POINT('',(0.,22.,-35.));
#1204=DIRECTION('',(0.,-1.,0.));
#1205=DIRECTION('',(0.,0.,-1.));
#1206=AXIS2_PLACEMENT_3D('',#1203,#1204,#1205);
#1207=CYLINDRICAL_SURFACE('',#1206,5.);
#1208=DIRECTION('',(0.,-1.,0.));
#1209=VECTOR('',#1208,1.);
#1210=CARTESIAN_POINT('',(5.00000000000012,22.,-35.));
#1211=LINE('',#1210,#1209);
#1212=CARTESIAN_POINT('',(5.00000000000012,10.8549409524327,-35.));
#1213=VERTEX_POINT('',#1212);
#1214=CARTESIAN_POINT('',(5.00000000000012,5.00000000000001,-35.));
#1215=VERTEX_POINT('',#1214);
#1216=EDGE_CURVE('E178',#1213,#1215,#1211,.T.);
#1217=ORIENTED_EDGE('',*,*,#1216,.T.);
#1218=CARTESIAN_POINT('',(0.,5.,-35.));
#1219=DIRECTION('',(0.,-1.,0.));
#1220=DIRECTION('',(0.,0.,-1.));
#1221=AXIS2_PLACEMENT_3D('',#1218,#1219,#1220);
#1222=CIRCLE('',#1221,5.);
#1223=EDGE_CURVE('E343',#1215,#1128,#1222,.F.);
#1224=ORIENTED_EDGE('',*,*,#1223,.T.);
#1225=ORIENTED_EDGE('',*,*,#1129,.F.);
#1226=CARTESIAN_POINT('',(0.,10.8549409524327,-35.));
#1227=DIRECTION('',(0.,-1.,0.));
#1228=DIRECTION('',(0.,0.,-1.));
#1229=AXIS2_PLACEMENT_3D('',#1226,#1227,#1228);
#1230=CIRCLE('',#1229,5.);
#1231=EDGE_CURVE('E523',#1126,#1213,#1230,.T.);
#1232=ORIENTED_EDGE('',*,*,#1231,.T.);
#1233=EDGE_LOOP('',(#1217,#1224,#1225,#1232));
#1234=FACE_BOUND('',#1233,.T.);
#1235=ADVANCED_FACE('F315',(#1234),#1207,.T.);
#1236=CARTESIAN_POINT('',(35.0000000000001,22.,-34.9999999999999));
#1237=DIRECTION('',(0.,-1.,0.));
#1238=DIRECTION('',(0.,0.,-1.));
#1239=AXIS2_PLACEMENT_3D('',#1236,#1237,#1238);
#1240=CYLINDRICAL_SURFACE('',#1239,30.);
#1241=DIRECTION('',(0.,-1.,0.));
#1242=VECTOR('',#1241,1.);
#1243=CARTESIAN_POINT('',(35.,22.,-4.99999999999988));
#1244=LINE('',#1243,#1242);
#1245=CARTESIAN_POINT('',(35.,10.8549409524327,-4.99999999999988));
#1246=VERTEX_POINT('',#1245);
#1247=CARTESIAN_POINT('',(35.,5.00000000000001,-4.99999999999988));
#1248=VERTEX_POINT('',#1247);
#1249=EDGE_CURVE('E174',#1246,#1248,#1244,.T.);
#1250=ORIENTED_EDGE('',*,*,#1249,.T.);
#1251=CARTESIAN_POINT('',(35.0000000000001,5.,-34.9999999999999));
#1252=DIRECTION('',(0.,1.,0.));
#1253=DIRECTION('',(0.,0.,1.));
#1254=AXIS2_PLACEMENT_3D('',#1251,#1252,#1253);
#1255=CIRCLE('',#1254,30.);
#1256=EDGE_CURVE('E326',#1248,#1215,#1255,.F.);
#1257=ORIENTED_EDGE('',*,*,#1256,.T.);
#1258=ORIENTED_EDGE('',*,*,#1216,.F.);
#1259=CARTESIAN_POINT('',(6.8699971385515,5.50948791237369,-45.4260701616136));
#1260=CARTESIAN_POINT('',(6.56923949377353,6.0070845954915,-44.614833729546));
#1261=CARTESIAN_POINT('',(6.30199730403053,6.49349722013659,-43.7858801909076));
#1262=CARTESIAN_POINT('',(5.83849231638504,7.44129663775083,-42.0973517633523));
#1263=CARTESIAN_POINT('',(5.64228458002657,7.90266378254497,-41.2377536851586));
#1264=CARTESIAN_POINT('',(5.32485383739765,8.7981236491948,-39.4917039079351));
#1265=CARTESIAN_POINT('',(5.20383148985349,9.23214063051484,-38.6051869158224));
#1266=CARTESIAN_POINT('',(5.04142115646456,10.068252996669,-36.8142382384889));
#1267=CARTESIAN_POINT('',(5.00000366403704,10.4703601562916,-35.909813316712));
#1268=CARTESIAN_POINT('',(4.99999689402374,11.1809471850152,-34.2287581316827));
#1269=CARTESIAN_POINT('',(5.02975303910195,11.494359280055,-33.4536442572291));
#1270=CARTESIAN_POINT('',(5.15038405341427,12.0940537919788,-31.9004971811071));
#1271=CARTESIAN_POINT('',(5.24125105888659,12.3803396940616,-31.1224643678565));
#1272=CARTESIAN_POINT('',(5.48506193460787,12.9234014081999,-29.5700101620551));
#1273=CARTESIAN_POINT('',(5.63789951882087,13.1802267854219,-28.7955848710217));
#1274=CARTESIAN_POINT('',(6.006270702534,13.6630595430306,-27.2546075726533));
#1275=CARTESIAN_POINT('',(6.22180091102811,13.8890685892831,-26.4880551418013));
#1276=CARTESIAN_POINT('',(6.69767385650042,14.2933454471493,-25.0236522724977));
#1277=CARTESIAN_POINT('',(6.95365023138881,14.4738834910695,-24.324841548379));
#1278=CARTESIAN_POINT('',(7.51897208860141,14.8056501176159,-22.9438952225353));
#1279=CARTESIAN_POINT('',(7.82831467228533,14.9568802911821,-22.2617587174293));
#1280=CARTESIAN_POINT('',(8.49935481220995,15.2289531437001,-20.9188278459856));
#1281=CARTESIAN_POINT('',(8.86106882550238,15.3497862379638,-20.2580402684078));
#1282=CARTESIAN_POINT('',(9.63505856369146,15.5600678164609,-18.9628904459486));
#1283=CARTESIAN_POINT('',(10.0473360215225,15.6495152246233,-18.3285291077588));
#1284=CARTESIAN_POINT('',(10.933284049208,15.7985146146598,-17.0723248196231));
#1285=CARTESIAN_POINT('',(11.4084308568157,15.8570839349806,-16.4514359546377));
#1286=CARTESIAN_POINT('',(12.4066932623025,15.9396337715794,-15.2476862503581));
#1287=CARTESIAN_POINT('',(12.9298092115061,15.9636140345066,-14.6648256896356));
#1288=CARTESIAN_POINT('',(14.0202983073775,15.9767747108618,-13.541553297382));
#1289=CARTESIAN_POINT('',(14.5876798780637,15.9659484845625,-13.0011495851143));
#1290=CARTESIAN_POINT('',(15.7622622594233,15.9095784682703,-11.9669404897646));
#1291=CARTESIAN_POINT('',(16.3694645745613,15.8640333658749,-11.4731368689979));
#1292=CARTESIAN_POINT('',(17.654931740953,15.7350022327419,-10.5085545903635));
#1293=CARTESIAN_POINT('',(18.3352752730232,15.6494810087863,-10.0407427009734));
#1294=CARTESIAN_POINT('',(19.7291109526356,15.4408611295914,-9.16440940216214));
#1295=CARTESIAN_POINT('',(20.4426048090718,15.3177605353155,-8.75589105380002));
#1296=CARTESIAN_POINT('',(21.8962711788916,15.0351629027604,-8.00068476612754));
#1297=CARTESIAN_POINT('',(22.6364376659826,14.8756740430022,-7.65398296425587));
#1298=CARTESIAN_POINT('',(24.1372364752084,14.5217101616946,-7.02388957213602));
#1299=CARTESIAN_POINT('',(24.8978685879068,14.3272354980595,-6.74049733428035));
#1300=CARTESIAN_POINT('',(26.4302760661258,13.9057857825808,-6.2387886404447));
#1301=CARTESIAN_POINT('',(27.2019951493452,13.6789429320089,-6.02021809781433));
#1302=CARTESIAN_POINT('',(28.7535086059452,13.1939765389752,-5.64666844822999));
#1303=CARTESIAN_POINT('',(29.5333029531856,12.9358530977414,-5.49168913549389));
#1304=CARTESIAN_POINT('',(31.0963614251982,12.3898447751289,-5.24452081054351));
#1305=CARTESIAN_POINT('',(31.8796288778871,12.101918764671,-5.15241994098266));
#1306=CARTESIAN_POINT('',(33.4432400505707,11.4985653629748,-5.03015412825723));
#1307=CARTESIAN_POINT('',(34.2235833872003,11.1831344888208,-4.99999704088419));
#1308=CARTESIAN_POINT('',(35.9097347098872,10.4703934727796,-5.0000034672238));
#1309=CARTESIAN_POINT('',(36.8140784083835,10.0683240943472,-5.04141375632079));
#1310=CARTESIAN_POINT('',(38.6048600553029,9.23229674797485,-5.20379475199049));
#1311=CARTESIAN_POINT('',(39.4912914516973,8.79832737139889,-5.32479404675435));
#1312=CARTESIAN_POINT('',(41.2373410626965,7.90288317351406,-5.64219442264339));
#1313=CARTESIAN_POINT('',(42.0970199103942,7.44147869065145,-5.83840915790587));
#1314=CARTESIAN_POINT('',(43.7857141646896,6.49359463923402,-6.30194379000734));
#1315=CARTESIAN_POINT('',(44.6147524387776,6.00713444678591,-6.56920938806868));
#1316=CARTESIAN_POINT('',(45.4260701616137,5.50948791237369,-6.86999713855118));
#1317=B_SPLINE_CURVE_WITH_KNOTS('',3,(#1259,#1260,#1261,#1262,#1263,#1264,#1265,#1266,#1267,
#1268,#1269,#1270,#1271,#1272,#1273,#1274,#1275,#1276,#1277,#1278,#1279,#1280,#1281,#1282,#1283,
#1284,#1285,#1286,#1287,#1288,#1289,#1290,#1291,#1292,#1293,#1294,#1295,#1296,#1297,#1298,#1299,
#1300,#1301,#1302,#1303,#1304,#1305,#1306,#1307,#1308,#1309,#1310,#1311,#1312,#1313,#1314,#1315,
#1316),.UNSPECIFIED.,.F.,.F.,(4,2,2,2,2,2,2,2,2,2,2,2,2,2,2,2,2,2,2,2,2,2,2,2,2,2,2,2,4),(0.,
3.37559024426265,6.75379146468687,10.1409703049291,13.5268934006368,16.3971148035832,
19.2669669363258,22.1319176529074,24.9967134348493,27.6543928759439,30.3119280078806,
32.9703000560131,35.6287632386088,38.367379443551,41.1060157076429,43.8451744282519,
46.5844366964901,49.4815561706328,52.3788251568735,55.2754436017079,58.1720324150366,
61.0571124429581,63.9421831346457,66.8312898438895,69.7207629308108,73.1063859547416,
76.4932257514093,79.8717283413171,83.2476563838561),.UNSPECIFIED.);
#1318=EDGE_CURVE('E319',#1213,#1246,#1317,.T.);
#1319=ORIENTED_EDGE('',*,*,#1318,.T.);
#1320=EDGE_LOOP('',(#1250,#1257,#1258,#1319));
#1321=FACE_BOUND('',#1320,.T.);
#1322=ADVANCED_FACE('F312',(#1321),#1240,.F.);
#1323=CARTESIAN_POINT('',(35.,22.,1.2220184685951E-13));
#1324=DIRECTION('',(0.,-1.,0.));
#1325=DIRECTION('',(0.,0.,-1.));
#1326=AXIS2_PLACEMENT_3D('',#1323,#1324,#1325);
#1327=CYLINDRICAL_SURFACE('',#1326,5.);
#1328=DIRECTION('',(0.,-1.,0.));
#1329=VECTOR('',#1328,1.);
#1330=CARTESIAN_POINT('',(35.,22.,5.00000000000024));
#1331=LINE('',#1330,#1329);
#1332=CARTESIAN_POINT('',(35.,10.8549409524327,5.00000000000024));
#1333=VERTEX_POINT('',#1332);
#1334=CARTESIAN_POINT('',(35.,5.00000000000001,5.00000000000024));
#1335=VERTEX_POINT('',#1334);
#1336=EDGE_CURVE('E166',#1333,#1335,#1331,.T.);
#1337=ORIENTED_EDGE('',*,*,#1336,.T.);
#1338=CARTESIAN_POINT('',(35.,5.,1.2220184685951E-13));
#1339=DIRECTION('',(0.,-1.,0.));
#1340=DIRECTION('',(0.,0.,-1.));
#1341=AXIS2_PLACEMENT_3D('',#1338,#1339,#1340);
#1342=CIRCLE('',#1341,5.);
#1343=EDGE_CURVE('E327',#1335,#1248,#1342,.F.);
#1344=ORIENTED_EDGE('',*,*,#1343,.T.);
#1345=ORIENTED_EDGE('',*,*,#1249,.F.);
#1346=CARTESIAN_POINT('',(35.,10.8549409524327,1.2220184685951E-13));
#1347=DIRECTION('',(0.,-1.,0.));
#1348=DIRECTION('',(0.,0.,-1.));
#1349=AXIS2_PLACEMENT_3D('',#1346,#1347,#1348);
#1350=CIRCLE('',#1349,5.);
#1351=EDGE_CURVE('E503',#1246,#1333,#1350,.T.);
#1352=ORIENTED_EDGE('',*,*,#1351,.T.);
#1353=EDGE_LOOP('',(#1337,#1344,#1345,#1352));
#1354=FACE_BOUND('',#1353,.T.);
#1355=ADVANCED_FACE('F239',(#1354),#1327,.T.);
#1356=CARTESIAN_POINT('',(34.9999999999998,22.,35.0000000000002));
#1357=DIRECTION('',(0.,-1.,0.));
#1358=DIRECTION('',(0.,0.,-1.));
#1359=AXIS2_PLACEMENT_3D('',#1356,#1357,#1358);
#1360=CYLINDRICAL_SURFACE('',#1359,30.);
#1361=DIRECTION('',(0.,-1.,0.));
#1362=VECTOR('',#1361,1.);
#1363=CARTESIAN_POINT('',(4.99999999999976,22.,35.));
#1364=LINE('',#1363,#1362);
#1365=CARTESIAN_POINT('',(4.99999999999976,10.8549409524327,35.));
#1366=VERTEX_POINT('',#1365);
#1367=CARTESIAN_POINT('',(4.99999999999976,5.00000000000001,35.));
#1368=VERTEX_POINT('',#1367);
#1369=EDGE_CURVE('E170',#1366,#1368,#1364,.T.);
#1370=ORIENTED_EDGE('',*,*,#1369,.T.);
#1371=CARTESIAN_POINT('',(34.9999999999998,5.,35.0000000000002));
#1372=DIRECTION('',(0.,1.,0.));
#1373=DIRECTION('',(0.,0.,1.));
#1374=AXIS2_PLACEMENT_3D('',#1371,#1372,#1373);
#1375=CIRCLE('',#1374,30.);
#1376=EDGE_CURVE('E227',#1368,#1335,#1375,.F.);
#1377=ORIENTED_EDGE('',*,*,#1376,.T.);
#1378=ORIENTED_EDGE('',*,*,#1336,.F.);
#1379=CARTESIAN_POINT('',(45.4260701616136,5.50948791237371,6.86999713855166));
#1380=CARTESIAN_POINT('',(44.6148337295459,6.0070845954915,6.56923949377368));
#1381=CARTESIAN_POINT('',(43.7858801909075,6.4934972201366,6.30199730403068));
#1382=CARTESIAN_POINT('',(42.0973517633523,7.44129663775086,5.83849231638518));
#1383=CARTESIAN_POINT('',(41.2377536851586,7.90266378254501,5.64228458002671));
#1384=CARTESIAN_POINT('',(39.491703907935,8.79812364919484,5.32485383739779));
#1385=CARTESIAN_POINT('',(38.6051869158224,9.23214063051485,5.20383148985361));
#1386=CARTESIAN_POINT('',(36.8142382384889,10.068252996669,5.04142115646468));
#1387=CARTESIAN_POINT('',(35.9098133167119,10.4703601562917,5.00000366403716));
#1388=CARTESIAN_POINT('',(34.2287581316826,11.1809471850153,4.99999689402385));
#1389=CARTESIAN_POINT('',(33.4536442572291,11.4943592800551,5.02975303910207));
#1390=CARTESIAN_POINT('',(31.900497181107,12.0940537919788,5.15038405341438));
#1391=CARTESIAN_POINT('',(31.1224643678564,12.3803396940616,5.24125105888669));
#1392=CARTESIAN_POINT('',(29.5700101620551,12.9234014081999,5.48506193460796));
#1393=CARTESIAN_POINT('',(28.7955848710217,13.1802267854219,5.63789951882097));
#1394=CARTESIAN_POINT('',(27.2546075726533,13.6630595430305,6.0062707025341));
#1395=CARTESIAN_POINT('',(26.4880551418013,13.8890685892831,6.22180091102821));
#1396=CARTESIAN_POINT('',(25.0236522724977,14.2933454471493,6.6976738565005));
#1397=CARTESIAN_POINT('',(24.324841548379,14.4738834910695,6.95365023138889));
#1398=CARTESIAN_POINT('',(22.9438952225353,14.8056501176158,7.51897208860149));
#1399=CARTESIAN_POINT('',(22.2617587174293,14.9568802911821,7.8283146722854));
#1400=CARTESIAN_POINT('',(20.9188278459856,15.2289531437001,8.49935481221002));
#1401=CARTESIAN_POINT('',(20.2580402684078,15.3497862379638,8.86106882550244));
#1402=CARTESIAN_POINT('',(18.9628904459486,15.5600678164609,9.63505856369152));
#1403=CARTESIAN_POINT('',(18.3285291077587,15.6495152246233,10.0473360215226));
#1404=CARTESIAN_POINT('',(17.0723248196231,15.7985146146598,10.933284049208));
#1405=CARTESIAN_POINT('',(16.4514359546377,15.8570839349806,11.4084308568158));
#1406=CARTESIAN_POINT('',(15.2476862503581,15.9396337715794,12.4066932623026));
#1407=CARTESIAN_POINT('',(14.6648256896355,15.9636140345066,12.9298092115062));
#1408=CARTESIAN_POINT('',(13.541553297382,15.9767747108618,14.0202983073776));
#1409=CARTESIAN_POINT('',(13.0011495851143,15.9659484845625,14.5876798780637));
#1410=CARTESIAN_POINT('',(11.9669404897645,15.9095784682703,15.7622622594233));
#1411=CARTESIAN_POINT('',(11.4731368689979,15.8640333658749,16.3694645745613));
#1412=CARTESIAN_POINT('',(10.5085545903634,15.7350022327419,17.654931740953));
#1413=CARTESIAN_POINT('',(10.0407427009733,15.6494810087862,18.3352752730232));
#1414=CARTESIAN_POINT('',(9.16440940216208,15.4408611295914,19.7291109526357));
#1415=CARTESIAN_POINT('',(8.75589105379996,15.3177605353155,20.4426048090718));
#1416=CARTESIAN_POINT('',(8.00068476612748,15.0351629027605,21.8962711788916));
#1417=CARTESIAN_POINT('',(7.65398296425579,14.8756740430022,22.6364376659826));
#1418=CARTESIAN_POINT('',(7.02388957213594,14.5217101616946,24.1372364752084));
#1419=CARTESIAN_POINT('',(6.74049733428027,14.3272354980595,24.8978685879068));
#1420=CARTESIAN_POINT('',(6.23878864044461,13.9057857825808,26.4302760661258));
#1421=CARTESIAN_POINT('',(6.02021809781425,13.6789429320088,27.2019951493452));
#1422=CARTESIAN_POINT('',(5.6466684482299,13.1939765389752,28.7535086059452));
#1423=CARTESIAN_POINT('',(5.49168913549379,12.9358530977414,29.5333029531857));
#1424=CARTESIAN_POINT('',(5.2445208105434,12.3898447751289,31.0963614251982));
#1425=CARTESIAN_POINT('',(5.15241994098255,12.101918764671,31.8796288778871));
#1426=CARTESIAN_POINT('',(5.03015412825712,11.4985653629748,33.4432400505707));
#1427=CARTESIAN_POINT('',(4.99999704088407,11.1831344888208,34.2235833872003));
#1428=CARTESIAN_POINT('',(5.00000346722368,10.4703934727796,35.9097347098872));
#1429=CARTESIAN_POINT('',(5.04141375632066,10.0683240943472,36.8140784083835));
#1430=CARTESIAN_POINT('',(5.20379475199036,9.23229674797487,38.6048600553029));
#1431=CARTESIAN_POINT('',(5.32479404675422,8.79832737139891,39.4912914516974));
#1432=CARTESIAN_POINT('',(5.64219442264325,7.90288317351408,41.2373410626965));
#1433=CARTESIAN_POINT('',(5.83840915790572,7.44147869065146,42.0970199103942));
#1434=CARTESIAN_POINT('',(6.30194379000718,6.49359463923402,43.7857141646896));
#1435=CARTESIAN_POINT('',(6.56920938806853,6.00713444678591,44.6147524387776));
#1436=CARTESIAN_POINT('',(6.86999713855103,5.50948791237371,45.4260701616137));
#1437=B_SPLINE_CURVE_WITH_KNOTS('',3,(#1379,#1380,#1381,#1382,#1383,#1384,#1385,#1386,#1387,
#1388,#1389,#1390,#1391,#1392,#1393,#1394,#1395,#1396,#1397,#1398,#1399,#1400,#1401,#1402,#1403,
#1404,#1405,#1406,#1407,#1408,#1409,#1410,#1411,#1412,#1413,#1414,#1415,#1416,#1417,#1418,#1419,
#1420,#1421,#1422,#1423,#1424,#1425,#1426,#1427,#1428,#1429,#1430,#1431,#1432,#1433,#1434,#1435,
#1436),.UNSPECIFIED.,.F.,.F.,(4,2,2,2,2,2,2,2,2,2,2,2,2,2,2,2,2,2,2,2,2,2,2,2,2,2,2,2,4),(0.,
3.37559024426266,6.75379146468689,10.1409703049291,13.5268934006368,16.3971148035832,
19.2669669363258,22.1319176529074,24.9967134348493,27.6543928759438,30.3119280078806,
32.9703000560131,35.6287632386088,38.3673794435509,41.1060157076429,43.8451744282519,
46.58443669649,49.4815561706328,52.3788251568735,55.2754436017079,58.1720324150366,
61.057112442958,63.9421831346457,66.8312898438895,69.7207629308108,73.1063859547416,
76.4932257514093,79.8717283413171,83.247656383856),.UNSPECIFIED.);
#1438=EDGE_CURVE('E219',#1333,#1366,#1437,.T.);
#1439=ORIENTED_EDGE('',*,*,#1438,.T.);
#1440=EDGE_LOOP('',(#1370,#1377,#1378,#1439));
#1441=FACE_BOUND('',#1440,.T.);
#1442=ADVANCED_FACE('F233',(#1441),#1360,.F.);
#1443=CARTESIAN_POINT('',(-2.44403693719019E-13,22.,35.));
#1444=DIRECTION('',(0.,-1.,0.));
#1445=DIRECTION('',(0.,0.,-1.));
#1446=AXIS2_PLACEMENT_3D('',#1443,#1444,#1445);
#1447=CYLINDRICAL_SURFACE('',#1446,5.);
#1448=DIRECTION('',(0.,-1.,0.));
#1449=VECTOR('',#1448,1.);
#1450=CARTESIAN_POINT('',(-5.00000000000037,22.,35.));
#1451=LINE('',#1450,#1449);
#1452=CARTESIAN_POINT('',(-5.00000000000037,10.8549409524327,35.));
#1453=VERTEX_POINT('',#1452);
#1454=CARTESIAN_POINT('',(-5.00000000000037,5.00000000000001,35.));
#1455=VERTEX_POINT('',#1454);
#1456=EDGE_CURVE('E157',#1453,#1455,#1451,.T.);
#1457=ORIENTED_EDGE('',*,*,#1456,.T.);
#1458=CARTESIAN_POINT('',(-2.44403693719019E-13,5.,35.));
#1459=DIRECTION('',(0.,-1.,0.));
#1460=DIRECTION('',(0.,0.,-1.));
#1461=AXIS2_PLACEMENT_3D('',#1458,#1459,#1460);
#1462=CIRCLE('',#1461,5.);
#1463=EDGE_CURVE('E202',#1455,#1368,#1462,.F.);
#1464=ORIENTED_EDGE('',*,*,#1463,.T.);
#1465=ORIENTED_EDGE('',*,*,#1369,.F.);
#1466=CARTESIAN_POINT('',(-2.44403693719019E-13,10.8549409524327,35.));
#1467=DIRECTION('',(0.,-1.,0.));
#1468=DIRECTION('',(0.,0.,-1.));
#1469=AXIS2_PLACEMENT_3D('',#1466,#1467,#1468);
#1470=CIRCLE('',#1469,5.);
#1471=EDGE_CURVE('E195',#1366,#1453,#1470,.T.);
#1472=ORIENTED_EDGE('',*,*,#1471,.T.);
#1473=EDGE_LOOP('',(#1457,#1464,#1465,#1472));
#1474=FACE_BOUND('',#1473,.T.);
#1475=ADVANCED_FACE('F238',(#1474),#1447,.T.);
#1476=CARTESIAN_POINT('',(-35.0000000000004,22.,34.9999999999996));
#1477=DIRECTION('',(0.,-1.,0.));
#1478=DIRECTION('',(0.,0.,-1.));
#1479=AXIS2_PLACEMENT_3D('',#1476,#1477,#1478);
#1480=CYLINDRICAL_SURFACE('',#1479,30.);
#1481=ORIENTED_EDGE('',*,*,#1104,.T.);
#1482=CARTESIAN_POINT('',(-35.0000000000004,5.,34.9999999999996));
#1483=DIRECTION('',(0.,1.,0.));
#1484=DIRECTION('',(0.,0.,1.));
#1485=AXIS2_PLACEMENT_3D('',#1482,#1483,#1484);
#1486=CIRCLE('',#1485,30.);
#1487=EDGE_CURVE('E11',#1095,#1455,#1486,.F.);
#1488=ORIENTED_EDGE('',*,*,#1487,.T.);
#1489=ORIENTED_EDGE('',*,*,#1456,.F.);
#1490=CARTESIAN_POINT('',(-6.86999713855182,5.50948791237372,45.4260701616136));
#1491=CARTESIAN_POINT('',(-6.56923949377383,6.00708459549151,44.6148337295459));
#1492=CARTESIAN_POINT('',(-6.30199730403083,6.49349722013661,43.7858801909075));
#1493=CARTESIAN_POINT('',(-5.83849231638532,7.44129663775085,42.0973517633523));
#1494=CARTESIAN_POINT('',(-5.64228458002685,7.90266378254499,41.2377536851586));
#1495=CARTESIAN_POINT('',(-5.32485383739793,8.79812364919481,39.491703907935));
#1496=CARTESIAN_POINT('',(-5.20383148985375,9.23214063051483,38.6051869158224));
#1497=CARTESIAN_POINT('',(-5.04142115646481,10.068252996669,36.8142382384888));
#1498=CARTESIAN_POINT('',(-5.00000366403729,10.4703601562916,35.9098133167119));
#1499=CARTESIAN_POINT('',(-4.99999689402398,11.1809471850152,34.2287581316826));
#1500=CARTESIAN_POINT('',(-5.02975303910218,11.494359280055,33.4536442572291));
#1501=CARTESIAN_POINT('',(-5.15038405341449,12.0940537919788,31.900497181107));
#1502=CARTESIAN_POINT('',(-5.2412510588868,12.3803396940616,31.1224643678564));
#1503=CARTESIAN_POINT('',(-5.48506193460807,12.9234014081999,29.570010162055));
#1504=CARTESIAN_POINT('',(-5.63789951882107,13.1802267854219,28.7955848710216));
#1505=CARTESIAN_POINT('',(-6.0062707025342,13.6630595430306,27.2546075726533));
#1506=CARTESIAN_POINT('',(-6.2218009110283,13.8890685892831,26.4880551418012));
#1507=CARTESIAN_POINT('',(-6.69767385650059,14.2933454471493,25.0236522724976));
#1508=CARTESIAN_POINT('',(-6.95365023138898,14.4738834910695,24.3248415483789));
#1509=CARTESIAN_POINT('',(-7.51897208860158,14.8056501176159,22.9438952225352));
#1510=CARTESIAN_POINT('',(-7.82831467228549,14.9568802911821,22.2617587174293));
#1511=CARTESIAN_POINT('',(-8.4993548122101,15.2289531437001,20.9188278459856));
#1512=CARTESIAN_POINT('',(-8.86106882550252,15.3497862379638,20.2580402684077));
#1513=CARTESIAN_POINT('',(-9.63505856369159,15.5600678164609,18.9628904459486));
#1514=CARTESIAN_POINT('',(-10.0473360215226,15.6495152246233,18.3285291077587));
#1515=CARTESIAN_POINT('',(-10.9332840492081,15.7985146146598,17.072324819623));
#1516=CARTESIAN_POINT('',(-11.4084308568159,15.8570839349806,16.4514359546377));
#1517=CARTESIAN_POINT('',(-12.4066932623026,15.9396337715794,15.247686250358));
#1518=CARTESIAN_POINT('',(-12.9298092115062,15.9636140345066,14.6648256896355));
#1519=CARTESIAN_POINT('',(-14.0202983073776,15.9767747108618,13.5415532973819));
#1520=CARTESIAN_POINT('',(-14.5876798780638,15.9659484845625,13.0011495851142));
#1521=CARTESIAN_POINT('',(-15.7622622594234,15.9095784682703,11.9669404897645));
#1522=CARTESIAN_POINT('',(-16.3694645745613,15.8640333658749,11.4731368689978));
#1523=CARTESIAN_POINT('',(-17.654931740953,15.7350022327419,10.5085545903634));
#1524=CARTESIAN_POINT('',(-18.3352752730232,15.6494810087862,10.0407427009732));
#1525=CARTESIAN_POINT('',(-19.7291109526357,15.4408611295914,9.16440940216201));
#1526=CARTESIAN_POINT('',(-20.4426048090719,15.3177605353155,8.75589105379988));
#1527=CARTESIAN_POINT('',(-21.8962711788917,15.0351629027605,8.00068476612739));
#1528=CARTESIAN_POINT('',(-22.6364376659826,14.8756740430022,7.65398296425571));
#1529=CARTESIAN_POINT('',(-24.1372364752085,14.5217101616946,7.02388957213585));
#1530=CARTESIAN_POINT('',(-24.8978685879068,14.3272354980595,6.74049733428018));
#1531=CARTESIAN_POINT('',(-26.4302760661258,13.9057857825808,6.23878864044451));
#1532=CARTESIAN_POINT('',(-27.2019951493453,13.6789429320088,6.02021809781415));
#1533=CARTESIAN_POINT('',(-28.7535086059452,13.1939765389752,5.6466684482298));
#1534=CARTESIAN_POINT('',(-29.5333029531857,12.9358530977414,5.49168913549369));
#1535=CARTESIAN_POINT('',(-31.0963614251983,12.3898447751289,5.24452081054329));
#1536=CARTESIAN_POINT('',(-31.8796288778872,12.101918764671,5.15241994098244));
#1537=CARTESIAN_POINT('',(-33.4432400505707,11.4985653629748,5.030154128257));
#1538=CARTESIAN_POINT('',(-34.2235833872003,11.1831344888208,4.99999704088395));
#1539=CARTESIAN_POINT('',(-35.9097347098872,10.4703934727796,5.00000346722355));
#1540=CARTESIAN_POINT('',(-36.8140784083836,10.0683240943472,5.04141375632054));
#1541=CARTESIAN_POINT('',(-38.6048600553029,9.23229674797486,5.20379475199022));
#1542=CARTESIAN_POINT('',(-39.4912914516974,8.7983273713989,5.32479404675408));
#1543=CARTESIAN_POINT('',(-41.2373410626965,7.90288317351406,5.6421944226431));
#1544=CARTESIAN_POINT('',(-42.0970199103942,7.44147869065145,5.83840915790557));
#1545=CARTESIAN_POINT('',(-43.7857141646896,6.49359463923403,6.30194379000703));
#1546=CARTESIAN_POINT('',(-44.6147524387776,6.00713444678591,6.56920938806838));
#1547=CARTESIAN_POINT('',(-45.4260701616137,5.50948791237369,6.86999713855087));
#1548=B_SPLINE_CURVE_WITH_KNOTS('',3,(#1490,#1491,#1492,#1493,#1494,#1495,#1496,#1497,#1498,
#1499,#1500,#1501,#1502,#1503,#1504,#1505,#1506,#1507,#1508,#1509,#1510,#1511,#1512,#1513,#1514,
#1515,#1516,#1517,#1518,#1519,#1520,#1521,#1522,#1523,#1524,#1525,#1526,#1527,#1528,#1529,#1530,
#1531,#1532,#1533,#1534,#1535,#1536,#1537,#1538,#1539,#1540,#1541,#1542,#1543,#1544,#1545,#1546,
#1547),.UNSPECIFIED.,.F.,.F.,(4,2,2,2,2,2,2,2,2,2,2,2,2,2,2,2,2,2,2,2,2,2,2,2,2,2,2,2,4),(0.,
3.37559024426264,6.75379146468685,10.1409703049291,13.5268934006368,16.3971148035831,
19.2669669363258,22.1319176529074,24.9967134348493,27.6543928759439,30.3119280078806,
32.9703000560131,35.6287632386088,38.3673794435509,41.1060157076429,43.8451744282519,
46.58443669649,49.4815561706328,52.3788251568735,55.2754436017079,58.1720324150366,
61.057112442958,63.9421831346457,66.8312898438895,69.7207629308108,73.1063859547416,
76.4932257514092,79.8717283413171,83.247656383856),.UNSPECIFIED.);
#1549=EDGE_CURVE('E53',#1453,#1103,#1548,.T.);
#1550=ORIENTED_EDGE('',*,*,#1549,.T.);
#1551=EDGE_LOOP('',(#1481,#1488,#1489,#1550));
#1552=FACE_BOUND('',#1551,.T.);
#1553=ADVANCED_FACE('F241',(#1552),#1480,.F.);
#1554=CARTESIAN_POINT('',(0.,5.,-35.));
#1555=DIRECTION('',(0.,0.,1.));
#1556=DIRECTION('',(1.,0.,0.));
#1557=AXIS2_PLACEMENT_3D('',#1554,#1555,#1556);
#1558=SPHERICAL_SURFACE('',#1557,5.);
#1559=CARTESIAN_POINT('',(0.,5.00000000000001,-35.));
#1560=DIRECTION('',(0.,0.,1.));
#1561=DIRECTION('',(1.,0.,0.));
#1562=AXIS2_PLACEMENT_3D('',#1559,#1560,#1561);
#1563=CIRCLE('',#1562,5.);
#1564=EDGE_CURVE('E408',#1128,#990,#1563,.T.);
#1565=ORIENTED_EDGE('',*,*,#1564,.F.);
#1566=ORIENTED_EDGE('',*,*,#1223,.F.);
#1567=CARTESIAN_POINT('',(0.,5.,-35.));
#1568=DIRECTION('',(0.,0.,1.));
#1569=DIRECTION('',(1.,0.,0.));
#1570=AXIS2_PLACEMENT_3D('',#1567,#1568,#1569);
#1571=CIRCLE('',#1570,5.);
#1572=EDGE_CURVE('E162',#990,#1215,#1571,.T.);
#1573=ORIENTED_EDGE('',*,*,#1572,.F.);
#1574=EDGE_LOOP('',(#1565,#1566,#1573));
#1575=FACE_BOUND('',#1574,.T.);
#1576=ADVANCED_FACE('F438',(#1575),#1558,.T.);
#1577=CARTESIAN_POINT('',(35.0000000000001,5.,-34.9999999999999));
#1578=DIRECTION('',(0.,1.,0.));
#1579=DIRECTION('',(0.,0.,1.));
#1580=AXIS2_PLACEMENT_3D('',#1577,#1578,#1579);
#1581=TOROIDAL_SURFACE('',#1580,35.,5.);
#1582=ORIENTED_EDGE('',*,*,#1572,.T.);
#1583=ORIENTED_EDGE('',*,*,#1256,.F.);
#1584=CARTESIAN_POINT('',(35.,5.,1.2220184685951E-13));
#1585=DIRECTION('',(1.,0.,0.));
#1586=DIRECTION('',(0.,0.,-1.));
#1587=AXIS2_PLACEMENT_3D('',#1584,#1585,#1586);
#1588=CIRCLE('',#1587,5.);
#1589=EDGE_CURVE('E404',#992,#1248,#1588,.T.);
#1590=ORIENTED_EDGE('',*,*,#1589,.F.);
#1591=ORIENTED_EDGE('',*,*,#993,.F.);
#1592=EDGE_LOOP('',(#1582,#1583,#1590,#1591));
#1593=FACE_BOUND('',#1592,.T.);
#1594=ADVANCED_FACE('F441',(#1593),#1581,.T.);
#1595=CARTESIAN_POINT('',(-35.,5.,-35.));
#1596=DIRECTION('',(0.,1.,0.));
#1597=DIRECTION('',(0.,0.,1.));
#1598=AXIS2_PLACEMENT_3D('',#1595,#1596,#1597);
#1599=TOROIDAL_SURFACE('',#1598,35.,5.);
#1600=ORIENTED_EDGE('',*,*,#1564,.T.);
#1601=ORIENTED_EDGE('',*,*,#1018,.F.);
#1602=CARTESIAN_POINT('',(-35.,5.,0.));
#1603=DIRECTION('',(-1.,0.,0.));
#1604=DIRECTION('',(0.,0.,1.));
#1605=AXIS2_PLACEMENT_3D('',#1602,#1603,#1604);
#1606=CIRCLE('',#1605,5.);
#1607=EDGE_CURVE('E400',#1086,#1010,#1606,.T.);
#1608=ORIENTED_EDGE('',*,*,#1607,.F.);
#1609=ORIENTED_EDGE('',*,*,#1136,.F.);
#1610=EDGE_LOOP('',(#1600,#1601,#1608,#1609));
#1611=FACE_BOUND('',#1610,.T.);
#1612=ADVANCED_FACE('F445',(#1611),#1599,.T.);
#1613=CARTESIAN_POINT('',(35.,5.,1.2220184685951E-13));
#1614=DIRECTION('',(0.,0.,1.));
#1615=DIRECTION('',(1.,0.,0.));
#1616=AXIS2_PLACEMENT_3D('',#1613,#1614,#1615);
#1617=SPHERICAL_SURFACE('',#1616,5.);
#1618=ORIENTED_EDGE('',*,*,#1589,.T.);
#1619=ORIENTED_EDGE('',*,*,#1343,.F.);
#1620=CARTESIAN_POINT('',(35.,5.,1.2220184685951E-13));
#1621=DIRECTION('',(-1.,0.,0.));
#1622=DIRECTION('',(0.,0.,1.));
#1623=AXIS2_PLACEMENT_3D('',#1620,#1621,#1622);
#1624=CIRCLE('',#1623,5.);
#1625=EDGE_CURVE('E396',#992,#1335,#1624,.T.);
#1626=ORIENTED_EDGE('',*,*,#1625,.F.);
#1627=EDGE_LOOP('',(#1618,#1619,#1626));
#1628=FACE_BOUND('',#1627,.T.);
#1629=ADVANCED_FACE('F449',(#1628),#1617,.T.);
#1630=CARTESIAN_POINT('',(-35.,5.,0.));
#1631=DIRECTION('',(0.,0.,1.));
#1632=DIRECTION('',(1.,0.,0.));
#1633=AXIS2_PLACEMENT_3D('',#1630,#1631,#1632);
#1634=SPHERICAL_SURFACE('',#1633,5.);
#1635=ORIENTED_EDGE('',*,*,#1096,.F.);
#1636=ORIENTED_EDGE('',*,*,#1607,.T.);
#1637=CARTESIAN_POINT('',(-35.,5.00000000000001,0.));
#1638=DIRECTION('',(1.,0.,0.));
#1639=DIRECTION('',(0.,0.,-1.));
#1640=AXIS2_PLACEMENT_3D('',#1637,#1638,#1639);
#1641=CIRCLE('',#1640,5.);
#1642=EDGE_CURVE('E392',#1095,#1010,#1641,.T.);
#1643=ORIENTED_EDGE('',*,*,#1642,.F.);
#1644=EDGE_LOOP('',(#1635,#1636,#1643));
#1645=FACE_BOUND('',#1644,.T.);
#1646=ADVANCED_FACE('F453',(#1645),#1634,.T.);
#1647=CARTESIAN_POINT('',(34.9999999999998,5.,35.0000000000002));
#1648=DIRECTION('',(0.,1.,0.));
#1649=DIRECTION('',(0.,0.,1.));
#1650=AXIS2_PLACEMENT_3D('',#1647,#1648,#1649);
#1651=TOROIDAL_SURFACE('',#1650,35.,5.);
#1652=ORIENTED_EDGE('',*,*,#1625,.T.);
#1653=ORIENTED_EDGE('',*,*,#1376,.F.);
#1654=CARTESIAN_POINT('',(-2.44403693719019E-13,5.,35.));
#1655=DIRECTION('',(0.,0.,1.));
#1656=DIRECTION('',(1.,0.,0.));
#1657=AXIS2_PLACEMENT_3D('',#1654,#1655,#1656);
#1658=CIRCLE('',#1657,5.);
#1659=EDGE_CURVE('E389',#1001,#1368,#1658,.T.);
#1660=ORIENTED_EDGE('',*,*,#1659,.F.);
#1661=ORIENTED_EDGE('',*,*,#1002,.F.);
#1662=EDGE_LOOP('',(#1652,#1653,#1660,#1661));
#1663=FACE_BOUND('',#1662,.T.);
#1664=ADVANCED_FACE('F457',(#1663),#1651,.T.);
#1665=CARTESIAN_POINT('',(-35.0000000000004,5.,34.9999999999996));
#1666=DIRECTION('',(0.,1.,0.));
#1667=DIRECTION('',(0.,0.,1.));
#1668=AXIS2_PLACEMENT_3D('',#1665,#1666,#1667);
#1669=TOROIDAL_SURFACE('',#1668,35.,5.);
#1670=ORIENTED_EDGE('',*,*,#1642,.T.);
#1671=ORIENTED_EDGE('',*,*,#1011,.F.);
#1672=CARTESIAN_POINT('',(-3.68628738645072E-13,5.,35.));
#1673=DIRECTION('',(0.,0.,1.));
#1674=DIRECTION('',(1.,0.,0.));
#1675=AXIS2_PLACEMENT_3D('',#1672,#1673,#1674);
#1676=CIRCLE('',#1675,5.);
#1677=EDGE_CURVE('E386',#1455,#1001,#1676,.T.);
#1678=ORIENTED_EDGE('',*,*,#1677,.F.);
#1679=ORIENTED_EDGE('',*,*,#1487,.F.);
#1680=EDGE_LOOP('',(#1670,#1671,#1678,#1679));
#1681=FACE_BOUND('',#1680,.T.);
#1682=ADVANCED_FACE('F461',(#1681),#1669,.T.);
#1683=CARTESIAN_POINT('',(-2.44403693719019E-13,5.,35.));
#1684=DIRECTION('',(0.,0.,1.));
#1685=DIRECTION('',(1.,0.,0.));
#1686=AXIS2_PLACEMENT_3D('',#1683,#1684,#1685);
#1687=SPHERICAL_SURFACE('',#1686,5.);
#1688=ORIENTED_EDGE('',*,*,#1659,.T.);
#1689=ORIENTED_EDGE('',*,*,#1463,.F.);
#1690=ORIENTED_EDGE('',*,*,#1677,.T.);
#1691=EDGE_LOOP('',(#1688,#1689,#1690));
#1692=FACE_BOUND('',#1691,.T.);
#1693=ADVANCED_FACE('F464',(#1692),#1687,.T.);
#1694=CARTESIAN_POINT('',(0.,10.8549409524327,-35.));
#1695=DIRECTION('',(0.,0.,1.));
#1696=DIRECTION('',(1.,0.,0.));
#1697=AXIS2_PLACEMENT_3D('',#1694,#1695,#1696);
#1698=SPHERICAL_SURFACE('',#1697,5.);
#1699=CARTESIAN_POINT('',(0.,10.8549409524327,-35.));
#1700=DIRECTION('',(0.,0.340645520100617,0.940191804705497));
#1701=DIRECTION('',(0.,-0.940191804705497,0.340645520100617));
#1702=AXIS2_PLACEMENT_3D('',#1699,#1700,#1701);
#1703=CIRCLE('',#1702,5.);
#1704=EDGE_CURVE('E302',#737,#1126,#1703,.T.);
#1705=ORIENTED_EDGE('',*,*,#1704,.F.);
#1706=CARTESIAN_POINT('',(0.,10.8549409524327,-35.));
#1707=DIRECTION('',(0.,0.340645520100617,0.940191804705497));
#1708=DIRECTION('',(0.,-0.940191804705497,0.340645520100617));
#1709=AXIS2_PLACEMENT_3D('',#1706,#1707,#1708);
#1710=CIRCLE('',#1709,5.);
#1711=EDGE_CURVE('E303',#1213,#737,#1710,.T.);
#1712=ORIENTED_EDGE('',*,*,#1711,.F.);
#1713=ORIENTED_EDGE('',*,*,#1231,.F.);
#1714=EDGE_LOOP('',(#1705,#1712,#1713));
#1715=FACE_BOUND('',#1714,.T.);
#1716=ADVANCED_FACE('F41',(#1715),#1698,.T.);
#1717=ORIENTED_EDGE('',*,*,#1711,.T.);
#1718=ORIENTED_EDGE('',*,*,#738,.F.);
#1719=CARTESIAN_POINT('',(35.,10.8549409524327,1.23165366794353E-13));
#1720=DIRECTION('',(0.940191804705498,-0.340645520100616,0.));
#1721=DIRECTION('',(0.340645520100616,0.940191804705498,0.));
#1722=AXIS2_PLACEMENT_3D('',#1719,#1720,#1721);
#1723=CIRCLE('',#1722,5.);
#1724=EDGE_CURVE('E508',#1246,#499,#1723,.T.);
#1725=ORIENTED_EDGE('',*,*,#1724,.F.);
#1726=ORIENTED_EDGE('',*,*,#1318,.F.);
#1727=EDGE_LOOP('',(#1717,#1718,#1725,#1726));
#1728=FACE_BOUND('',#1727,.T.);
#1729=ADVANCED_FACE('F287',(#1728),#676,.T.);
#1730=ORIENTED_EDGE('',*,*,#1704,.T.);
#1731=ORIENTED_EDGE('',*,*,#1198,.F.);
#1732=CARTESIAN_POINT('',(-35.,10.8549409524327,0.));
#1733=DIRECTION('',(-0.940191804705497,-0.340645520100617,0.));
#1734=DIRECTION('',(0.340645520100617,-0.940191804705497,0.));
#1735=AXIS2_PLACEMENT_3D('',#1732,#1733,#1734);
#1736=CIRCLE('',#1735,5.);
#1737=EDGE_CURVE('E270',#259,#1084,#1736,.T.);
#1738=ORIENTED_EDGE('',*,*,#1737,.F.);
#1739=ORIENTED_EDGE('',*,*,#974,.F.);
#1740=EDGE_LOOP('',(#1730,#1731,#1738,#1739));
#1741=FACE_BOUND('',#1740,.T.);
#1742=ADVANCED_FACE('F280',(#1741),#914,.T.);
#1743=CARTESIAN_POINT('',(35.,10.8549409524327,1.2220184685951E-13));
#1744=DIRECTION('',(0.,0.,1.));
#1745=DIRECTION('',(1.,0.,0.));
#1746=AXIS2_PLACEMENT_3D('',#1743,#1744,#1745);
#1747=SPHERICAL_SURFACE('',#1746,5.);
#1748=ORIENTED_EDGE('',*,*,#1351,.F.);
#1749=ORIENTED_EDGE('',*,*,#1724,.T.);
#1750=CARTESIAN_POINT('',(35.,10.8549409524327,1.21430643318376E-13));
#1751=DIRECTION('',(-0.940191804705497,0.340645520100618,0.));
#1752=DIRECTION('',(-0.340645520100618,-0.940191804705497,0.));
#1753=AXIS2_PLACEMENT_3D('',#1750,#1751,#1752);
#1754=CIRCLE('',#1753,5.);
#1755=EDGE_CURVE('E61',#1333,#499,#1754,.T.);
#1756=ORIENTED_EDGE('',*,*,#1755,.F.);
#1757=EDGE_LOOP('',(#1748,#1749,#1756));
#1758=FACE_BOUND('',#1757,.T.);
#1759=ADVANCED_FACE('F276',(#1758),#1747,.T.);
#1760=CARTESIAN_POINT('',(-35.,10.8549409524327,0.));
#1761=DIRECTION('',(0.,0.,1.));
#1762=DIRECTION('',(1.,0.,0.));
#1763=AXIS2_PLACEMENT_3D('',#1760,#1761,#1762);
#1764=SPHERICAL_SURFACE('',#1763,5.);
#1765=ORIENTED_EDGE('',*,*,#1737,.T.);
#1766=ORIENTED_EDGE('',*,*,#1111,.F.);
#1767=CARTESIAN_POINT('',(-35.,10.8549409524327,0.));
#1768=DIRECTION('',(0.940191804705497,0.340645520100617,0.));
#1769=DIRECTION('',(-0.340645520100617,0.940191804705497,0.));
#1770=AXIS2_PLACEMENT_3D('',#1767,#1768,#1769);
#1771=CIRCLE('',#1770,5.);
#1772=EDGE_CURVE('E421',#259,#1103,#1771,.T.);
#1773=ORIENTED_EDGE('',*,*,#1772,.F.);
#1774=EDGE_LOOP('',(#1765,#1766,#1773));
#1775=FACE_BOUND('',#1774,.T.);
#1776=ADVANCED_FACE('F254',(#1775),#1764,.T.);
#1777=ORIENTED_EDGE('',*,*,#1755,.T.);
#1778=ORIENTED_EDGE('',*,*,#500,.F.);
#1779=CARTESIAN_POINT('',(-2.41993924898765E-13,10.8549409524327,35.));
#1780=DIRECTION('',(0.,-0.340645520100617,0.940191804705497));
#1781=DIRECTION('',(0.,-0.940191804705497,-0.340645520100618));
#1782=AXIS2_PLACEMENT_3D('',#1779,#1780,#1781);
#1783=CIRCLE('',#1782,5.);
#1784=EDGE_CURVE('E417',#1366,#261,#1783,.T.);
#1785=ORIENTED_EDGE('',*,*,#1784,.F.);
#1786=ORIENTED_EDGE('',*,*,#1438,.F.);
#1787=EDGE_LOOP('',(#1777,#1778,#1785,#1786));
#1788=FACE_BOUND('',#1787,.T.);
#1789=ADVANCED_FACE('F246',(#1788),#438,.T.);
#1790=ORIENTED_EDGE('',*,*,#1772,.T.);
#1791=ORIENTED_EDGE('',*,*,#1549,.F.);
#1792=CARTESIAN_POINT('',(-3.70171145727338E-13,10.8549409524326,35.));
#1793=DIRECTION('',(0.,-0.340645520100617,0.940191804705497));
#1794=DIRECTION('',(0.,-0.940191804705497,-0.340645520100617));
#1795=AXIS2_PLACEMENT_3D('',#1792,#1793,#1794);
#1796=CIRCLE('',#1795,5.);
#1797=EDGE_CURVE('E154',#261,#1453,#1796,.T.);
#1798=ORIENTED_EDGE('',*,*,#1797,.F.);
#1799=ORIENTED_EDGE('',*,*,#262,.F.);
#1800=EDGE_LOOP('',(#1790,#1791,#1798,#1799));
#1801=FACE_BOUND('',#1800,.T.);
#1802=ADVANCED_FACE('F253',(#1801),#198,.T.);
#1803=CARTESIAN_POINT('',(-2.44403693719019E-13,10.8549409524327,35.));
#1804=DIRECTION('',(0.,0.,1.));
#1805=DIRECTION('',(1.,0.,0.));
#1806=AXIS2_PLACEMENT_3D('',#1803,#1804,#1805);
#1807=SPHERICAL_SURFACE('',#1806,5.);
#1808=ORIENTED_EDGE('',*,*,#1471,.F.);
#1809=ORIENTED_EDGE('',*,*,#1784,.T.);
#1810=ORIENTED_EDGE('',*,*,#1797,.T.);
#1811=EDGE_LOOP('',(#1808,#1809,#1810));
#1812=FACE_BOUND('',#1811,.T.);
#1813=ADVANCED_FACE('F432',(#1812),#1807,.T.);
#1814=CARTESIAN_POINT('',(0.,4.,0.));
#1815=DIRECTION('',(0.,-1.,0.));
#1816=DIRECTION('',(0.,0.,-1.));
#1817=AXIS2_PLACEMENT_3D('',#1814,#1815,#1816);
#1818=CYLINDRICAL_SURFACE('',#1817,8.);
#1819=CARTESIAN_POINT('',(0.,4.,0.));
#1820=DIRECTION('',(0.,1.,0.));
#1821=DIRECTION('',(-1.,0.,0.));
#1822=AXIS2_PLACEMENT_3D('',#1819,#1820,#1821);
#1823=CIRCLE('',#1822,8.);
#1824=CARTESIAN_POINT('',(-8.,4.,0.));
#1825=VERTEX_POINT('',#1824);
#1826=EDGE_CURVE('E145',#1825,#1825,#1823,.T.);
#1827=ORIENTED_EDGE('',*,*,#1826,.T.);
#1828=EDGE_LOOP('',(#1827));
#1829=FACE_BOUND('',#1828,.T.);
#1830=ORIENTED_EDGE('',*,*,#1066,.T.);
#1831=EDGE_LOOP('',(#1830));
#1832=FACE_BOUND('',#1831,.T.);
#1833=ADVANCED_FACE('F141',(#1829,#1832),#1818,.F.);
#1834=CARTESIAN_POINT('',(0.,4.,0.));
#1835=DIRECTION('',(0.,-1.,0.));
#1836=DIRECTION('',(1.,0.,0.));
#1837=AXIS2_PLACEMENT_3D('',#1834,#1835,#1836);
#1838=CONICAL_SURFACE('',#1837,8.,1.0471975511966);
#1839=CARTESIAN_POINT('',(0.,8.61880215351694,0.));
#1840=VERTEX_POINT('',#1839);
#1841=VERTEX_LOOP('',#1840);
#1842=FACE_BOUND('',#1841,.T.);
#1843=ORIENTED_EDGE('',*,*,#1826,.F.);
#1844=EDGE_LOOP('',(#1843));
#1845=FACE_BOUND('',#1844,.T.);
#1846=ADVANCED_FACE('F138',(#1842,#1845),#1838,.F.);
#1847=CLOSED_SHELL('',(#978,#1033,#1053,#1073,#1115,#1202,#1235,#1322,#1355,#1442,#1475,#1553,
#1576,#1594,#1612,#1629,#1646,#1664,#1682,#1693,#1716,#1729,#1742,#1759,#1776,#1789,#1802,#1813,
#1833,#1846));
#1848=MANIFOLD_SOLID_BREP('B2',#1847);
#1849=ADVANCED_BREP_SHAPE_REPRESENTATION('',(#18,#1848),#14);
#1850=SHAPE_DEFINITION_REPRESENTATION(#9,#1849);
ENDSEC;
END-ISO-10303-21;
